VERSION 5.7 ;
  NOWIREEXTENSIONATPIN ON ;
  DIVIDERCHAR "/" ;
  BUSBITCHARS "[]" ;
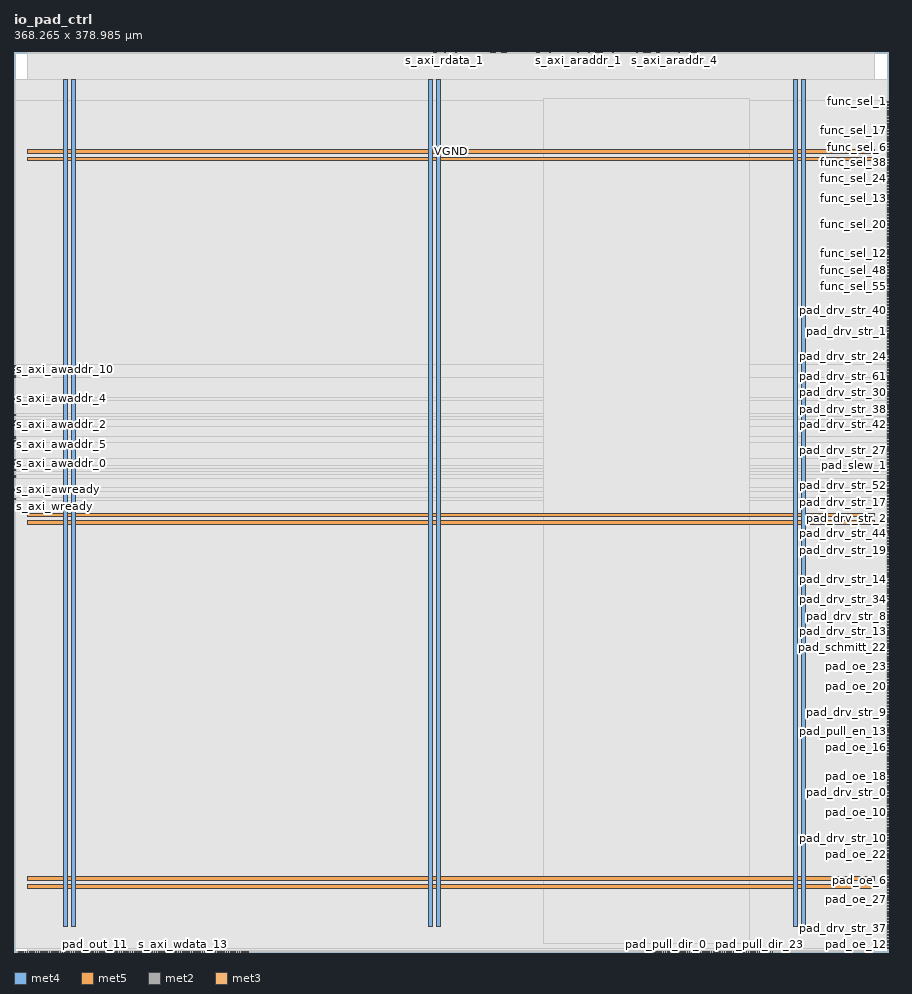
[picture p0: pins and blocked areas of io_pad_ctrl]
MACRO io_pad_ctrl
  CLASS BLOCK ;
  FOREIGN io_pad_ctrl ;
  ORIGIN 0.000 0.000 ;
  SIZE 368.265 BY 378.985 ;
  PIN VGND
    DIRECTION INOUT ;
    USE GROUND ;
    PORT
      LAYER met4 ;
        RECT 24.340 10.640 25.940 367.440 ;
    END
    PORT
      LAYER met4 ;
        RECT 177.940 10.640 179.540 367.440 ;
    END
    PORT
      LAYER met4 ;
        RECT 331.540 10.640 333.140 367.440 ;
    END
    PORT
      LAYER met5 ;
        RECT 5.520 30.030 362.480 31.630 ;
    END
    PORT
      LAYER met5 ;
        RECT 5.520 183.210 362.480 184.810 ;
    END
    PORT
      LAYER met5 ;
        RECT 5.520 336.390 362.480 337.990 ;
    END
  END VGND
  PIN VPWR
    DIRECTION INOUT ;
    USE POWER ;
    PORT
      LAYER met4 ;
        RECT 21.040 10.640 22.640 367.440 ;
    END
    PORT
      LAYER met4 ;
        RECT 174.640 10.640 176.240 367.440 ;
    END
    PORT
      LAYER met4 ;
        RECT 328.240 10.640 329.840 367.440 ;
    END
    PORT
      LAYER met5 ;
        RECT 5.520 26.730 362.480 28.330 ;
    END
    PORT
      LAYER met5 ;
        RECT 5.520 179.910 362.480 181.510 ;
    END
    PORT
      LAYER met5 ;
        RECT 5.520 333.090 362.480 334.690 ;
    END
  END VPWR
  PIN clk
    DIRECTION INPUT ;
    USE SIGNAL ;
    ANTENNAGATEAREA 1.286700 ;
    ANTENNADIFFAREA 0.434700 ;
    PORT
      LAYER met2 ;
        RECT 36.890 0.000 37.170 0.280 ;
    END
  END clk
  PIN func_sel_0
    DIRECTION OUTPUT ;
    USE SIGNAL ;
    ANTENNAGATEAREA 0.434700 ;
    ANTENNADIFFAREA 0.775300 ;
    PORT
      LAYER met3 ;
        RECT 367.665 243.480 368.265 244.080 ;
    END
  END func_sel_0
  PIN func_sel_1
    DIRECTION OUTPUT ;
    USE SIGNAL ;
    ANTENNAGATEAREA 0.434700 ;
    ANTENNADIFFAREA 0.775300 ;
    PORT
      LAYER met3 ;
        RECT 367.665 357.720 368.265 358.320 ;
    END
  END func_sel_1
  PIN func_sel_10
    DIRECTION OUTPUT ;
    USE SIGNAL ;
    ANTENNAGATEAREA 0.434700 ;
    ANTENNADIFFAREA 0.775300 ;
    PORT
      LAYER met3 ;
        RECT 367.665 341.400 368.265 342.000 ;
    END
  END func_sel_10
  PIN func_sel_11
    DIRECTION OUTPUT ;
    USE SIGNAL ;
    ANTENNAGATEAREA 0.434700 ;
    ANTENNADIFFAREA 0.775300 ;
    PORT
      LAYER met3 ;
        RECT 367.665 287.000 368.265 287.600 ;
    END
  END func_sel_11
  PIN func_sel_12
    DIRECTION OUTPUT ;
    USE SIGNAL ;
    ANTENNAGATEAREA 0.434700 ;
    ANTENNADIFFAREA 0.775300 ;
    PORT
      LAYER met3 ;
        RECT 367.665 293.800 368.265 294.400 ;
    END
  END func_sel_12
  PIN func_sel_13
    DIRECTION OUTPUT ;
    USE SIGNAL ;
    ANTENNAGATEAREA 0.434700 ;
    ANTENNADIFFAREA 0.775300 ;
    PORT
      LAYER met3 ;
        RECT 367.665 316.920 368.265 317.520 ;
    END
  END func_sel_13
  PIN func_sel_14
    DIRECTION OUTPUT ;
    USE SIGNAL ;
    ANTENNAGATEAREA 0.434700 ;
    ANTENNADIFFAREA 0.775300 ;
    PORT
      LAYER met3 ;
        RECT 367.665 342.760 368.265 343.360 ;
    END
  END func_sel_14
  PIN func_sel_15
    DIRECTION OUTPUT ;
    USE SIGNAL ;
    ANTENNAGATEAREA 0.434700 ;
    ANTENNADIFFAREA 0.775300 ;
    PORT
      LAYER met3 ;
        RECT 367.665 274.760 368.265 275.360 ;
    END
  END func_sel_15
  PIN func_sel_16
    DIRECTION OUTPUT ;
    USE SIGNAL ;
    ANTENNAGATEAREA 0.434700 ;
    ANTENNADIFFAREA 0.775300 ;
    PORT
      LAYER met3 ;
        RECT 367.665 318.280 368.265 318.880 ;
    END
  END func_sel_16
  PIN func_sel_17
    DIRECTION OUTPUT ;
    USE SIGNAL ;
    ANTENNAGATEAREA 0.434700 ;
    ANTENNADIFFAREA 0.775300 ;
    PORT
      LAYER met3 ;
        RECT 367.665 345.480 368.265 346.080 ;
    END
  END func_sel_17
  PIN func_sel_18
    DIRECTION OUTPUT ;
    USE SIGNAL ;
    ANTENNAGATEAREA 0.434700 ;
    ANTENNADIFFAREA 0.775300 ;
    PORT
      LAYER met3 ;
        RECT 367.665 344.120 368.265 344.720 ;
    END
  END func_sel_18
  PIN func_sel_19
    DIRECTION OUTPUT ;
    USE SIGNAL ;
    ANTENNAGATEAREA 0.434700 ;
    ANTENNADIFFAREA 0.775300 ;
    PORT
      LAYER met3 ;
        RECT 367.665 319.640 368.265 320.240 ;
    END
  END func_sel_19
  PIN func_sel_2
    DIRECTION OUTPUT ;
    USE SIGNAL ;
    ANTENNAGATEAREA 0.434700 ;
    ANTENNADIFFAREA 0.775300 ;
    PORT
      LAYER met3 ;
        RECT 367.665 280.200 368.265 280.800 ;
    END
  END func_sel_2
  PIN func_sel_20
    DIRECTION OUTPUT ;
    USE SIGNAL ;
    ANTENNAGATEAREA 0.434700 ;
    ANTENNADIFFAREA 0.775300 ;
    PORT
      LAYER met3 ;
        RECT 367.665 306.040 368.265 306.640 ;
    END
  END func_sel_20
  PIN func_sel_21
    DIRECTION OUTPUT ;
    USE SIGNAL ;
    ANTENNAGATEAREA 0.434700 ;
    ANTENNADIFFAREA 0.775300 ;
    PORT
      LAYER met3 ;
        RECT 367.665 352.280 368.265 352.880 ;
    END
  END func_sel_21
  PIN func_sel_22
    DIRECTION OUTPUT ;
    USE SIGNAL ;
    ANTENNAGATEAREA 0.434700 ;
    ANTENNADIFFAREA 0.775300 ;
    PORT
      LAYER met3 ;
        RECT 367.665 331.880 368.265 332.480 ;
    END
  END func_sel_22
  PIN func_sel_23
    DIRECTION OUTPUT ;
    USE SIGNAL ;
    ANTENNAGATEAREA 0.434700 ;
    ANTENNADIFFAREA 0.775300 ;
    PORT
      LAYER met3 ;
        RECT 367.665 301.960 368.265 302.560 ;
    END
  END func_sel_23
  PIN func_sel_24
    DIRECTION OUTPUT ;
    USE SIGNAL ;
    ANTENNAGATEAREA 0.434700 ;
    ANTENNADIFFAREA 0.775300 ;
    PORT
      LAYER met3 ;
        RECT 367.665 322.360 368.265 322.960 ;
    END
  END func_sel_24
  PIN func_sel_25
    DIRECTION OUTPUT ;
    USE SIGNAL ;
    ANTENNAGATEAREA 0.434700 ;
    ANTENNADIFFAREA 0.775300 ;
    PORT
      LAYER met3 ;
        RECT 367.665 346.840 368.265 347.440 ;
    END
  END func_sel_25
  PIN func_sel_26
    DIRECTION OUTPUT ;
    USE SIGNAL ;
    ANTENNAGATEAREA 0.434700 ;
    ANTENNADIFFAREA 0.775300 ;
    PORT
      LAYER met3 ;
        RECT 367.665 348.200 368.265 348.800 ;
    END
  END func_sel_26
  PIN func_sel_27
    DIRECTION OUTPUT ;
    USE SIGNAL ;
    ANTENNAGATEAREA 0.434700 ;
    ANTENNADIFFAREA 0.775300 ;
    PORT
      LAYER met3 ;
        RECT 367.665 323.720 368.265 324.320 ;
    END
  END func_sel_27
  PIN func_sel_28
    DIRECTION OUTPUT ;
    USE SIGNAL ;
    ANTENNAGATEAREA 0.434700 ;
    ANTENNADIFFAREA 0.775300 ;
    PORT
      LAYER met3 ;
        RECT 367.665 307.400 368.265 308.000 ;
    END
  END func_sel_28
  PIN func_sel_29
    DIRECTION OUTPUT ;
    USE SIGNAL ;
    ANTENNAGATEAREA 0.434700 ;
    ANTENNADIFFAREA 0.775300 ;
    PORT
      LAYER met3 ;
        RECT 367.665 291.080 368.265 291.680 ;
    END
  END func_sel_29
  PIN func_sel_3
    DIRECTION OUTPUT ;
    USE SIGNAL ;
    ANTENNAGATEAREA 0.434700 ;
    ANTENNADIFFAREA 0.775300 ;
    PORT
      LAYER met3 ;
        RECT 367.665 353.640 368.265 354.240 ;
    END
  END func_sel_3
  PIN func_sel_30
    DIRECTION OUTPUT ;
    USE SIGNAL ;
    ANTENNAGATEAREA 0.434700 ;
    ANTENNADIFFAREA 0.775300 ;
    PORT
      LAYER met3 ;
        RECT 367.665 292.440 368.265 293.040 ;
    END
  END func_sel_30
  PIN func_sel_31
    DIRECTION OUTPUT ;
    USE SIGNAL ;
    ANTENNAGATEAREA 0.434700 ;
    ANTENNADIFFAREA 0.775300 ;
    PORT
      LAYER met3 ;
        RECT 367.665 276.120 368.265 276.720 ;
    END
  END func_sel_31
  PIN func_sel_32
    DIRECTION OUTPUT ;
    USE SIGNAL ;
    ANTENNAGATEAREA 0.434700 ;
    ANTENNADIFFAREA 0.775300 ;
    PORT
      LAYER met3 ;
        RECT 367.665 326.440 368.265 327.040 ;
    END
  END func_sel_32
  PIN func_sel_33
    DIRECTION OUTPUT ;
    USE SIGNAL ;
    ANTENNAGATEAREA 0.434700 ;
    ANTENNADIFFAREA 0.775300 ;
    PORT
      LAYER met3 ;
        RECT 367.665 310.120 368.265 310.720 ;
    END
  END func_sel_33
  PIN func_sel_34
    DIRECTION OUTPUT ;
    USE SIGNAL ;
    ANTENNAGATEAREA 0.434700 ;
    ANTENNADIFFAREA 0.775300 ;
    PORT
      LAYER met3 ;
        RECT 367.665 349.560 368.265 350.160 ;
    END
  END func_sel_34
  PIN func_sel_35
    DIRECTION OUTPUT ;
    USE SIGNAL ;
    ANTENNAGATEAREA 0.434700 ;
    ANTENNADIFFAREA 0.775300 ;
    PORT
      LAYER met3 ;
        RECT 367.665 327.800 368.265 328.400 ;
    END
  END func_sel_35
  PIN func_sel_36
    DIRECTION OUTPUT ;
    USE SIGNAL ;
    ANTENNAGATEAREA 0.434700 ;
    ANTENNADIFFAREA 0.775300 ;
    PORT
      LAYER met3 ;
        RECT 367.665 295.160 368.265 295.760 ;
    END
  END func_sel_36
  PIN func_sel_37
    DIRECTION OUTPUT ;
    USE SIGNAL ;
    ANTENNAGATEAREA 0.434700 ;
    ANTENNADIFFAREA 0.775300 ;
    PORT
      LAYER met3 ;
        RECT 367.665 297.880 368.265 298.480 ;
    END
  END func_sel_37
  PIN func_sel_38
    DIRECTION OUTPUT ;
    USE SIGNAL ;
    ANTENNAGATEAREA 0.434700 ;
    ANTENNADIFFAREA 0.775300 ;
    PORT
      LAYER met3 ;
        RECT 367.665 329.160 368.265 329.760 ;
    END
  END func_sel_38
  PIN func_sel_39
    DIRECTION OUTPUT ;
    USE SIGNAL ;
    ANTENNAGATEAREA 0.434700 ;
    ANTENNADIFFAREA 0.775300 ;
    PORT
      LAYER met3 ;
        RECT 367.665 312.840 368.265 313.440 ;
    END
  END func_sel_39
  PIN func_sel_4
    DIRECTION OUTPUT ;
    USE SIGNAL ;
    ANTENNAGATEAREA 0.434700 ;
    ANTENNADIFFAREA 0.775300 ;
    PORT
      LAYER met3 ;
        RECT 367.665 296.520 368.265 297.120 ;
    END
  END func_sel_4
  PIN func_sel_40
    DIRECTION OUTPUT ;
    USE SIGNAL ;
    ANTENNAGATEAREA 0.434700 ;
    ANTENNADIFFAREA 0.775300 ;
    PORT
      LAYER met3 ;
        RECT 367.665 330.520 368.265 331.120 ;
    END
  END func_sel_40
  PIN func_sel_41
    DIRECTION OUTPUT ;
    USE SIGNAL ;
    ANTENNAGATEAREA 0.434700 ;
    ANTENNADIFFAREA 0.775300 ;
    PORT
      LAYER met3 ;
        RECT 367.665 355.000 368.265 355.600 ;
    END
  END func_sel_41
  PIN func_sel_42
    DIRECTION OUTPUT ;
    USE SIGNAL ;
    ANTENNAGATEAREA 0.434700 ;
    ANTENNADIFFAREA 0.775300 ;
    PORT
      LAYER met3 ;
        RECT 367.665 281.560 368.265 282.160 ;
    END
  END func_sel_42
  PIN func_sel_43
    DIRECTION OUTPUT ;
    USE SIGNAL ;
    ANTENNAGATEAREA 0.434700 ;
    ANTENNADIFFAREA 0.775300 ;
    PORT
      LAYER met3 ;
        RECT 367.665 356.360 368.265 356.960 ;
    END
  END func_sel_43
  PIN func_sel_44
    DIRECTION OUTPUT ;
    USE SIGNAL ;
    ANTENNAGATEAREA 0.434700 ;
    ANTENNADIFFAREA 0.775300 ;
    PORT
      LAYER met3 ;
        RECT 367.665 315.560 368.265 316.160 ;
    END
  END func_sel_44
  PIN func_sel_45
    DIRECTION OUTPUT ;
    USE SIGNAL ;
    ANTENNAGATEAREA 0.434700 ;
    ANTENNADIFFAREA 0.775300 ;
    PORT
      LAYER met3 ;
        RECT 367.665 299.240 368.265 299.840 ;
    END
  END func_sel_45
  PIN func_sel_46
    DIRECTION OUTPUT ;
    USE SIGNAL ;
    ANTENNAGATEAREA 0.434700 ;
    ANTENNADIFFAREA 0.775300 ;
    PORT
      LAYER met3 ;
        RECT 367.665 333.240 368.265 333.840 ;
    END
  END func_sel_46
  PIN func_sel_47
    DIRECTION OUTPUT ;
    USE SIGNAL ;
    ANTENNAGATEAREA 0.434700 ;
    ANTENNADIFFAREA 0.775300 ;
    PORT
      LAYER met3 ;
        RECT 367.665 300.600 368.265 301.200 ;
    END
  END func_sel_47
  PIN func_sel_48
    DIRECTION OUTPUT ;
    USE SIGNAL ;
    ANTENNAGATEAREA 0.434700 ;
    ANTENNADIFFAREA 0.775300 ;
    PORT
      LAYER met3 ;
        RECT 367.665 289.720 368.265 290.320 ;
    END
  END func_sel_48
  PIN func_sel_49
    DIRECTION OUTPUT ;
    USE SIGNAL ;
    ANTENNAGATEAREA 0.434700 ;
    ANTENNADIFFAREA 0.775300 ;
    PORT
      LAYER met3 ;
        RECT 367.665 334.600 368.265 335.200 ;
    END
  END func_sel_49
  PIN func_sel_5
    DIRECTION OUTPUT ;
    USE SIGNAL ;
    ANTENNAGATEAREA 0.434700 ;
    ANTENNADIFFAREA 0.775300 ;
    PORT
      LAYER met3 ;
        RECT 367.665 304.680 368.265 305.280 ;
    END
  END func_sel_5
  PIN func_sel_50
    DIRECTION OUTPUT ;
    USE SIGNAL ;
    ANTENNAGATEAREA 0.434700 ;
    ANTENNADIFFAREA 0.775300 ;
    PORT
      LAYER met3 ;
        RECT 367.665 303.320 368.265 303.920 ;
    END
  END func_sel_50
  PIN func_sel_51
    DIRECTION OUTPUT ;
    USE SIGNAL ;
    ANTENNAGATEAREA 0.434700 ;
    ANTENNADIFFAREA 0.775300 ;
    PORT
      LAYER met3 ;
        RECT 367.665 278.840 368.265 279.440 ;
    END
  END func_sel_51
  PIN func_sel_52
    DIRECTION OUTPUT ;
    USE SIGNAL ;
    ANTENNAGATEAREA 0.434700 ;
    ANTENNADIFFAREA 0.775300 ;
    PORT
      LAYER met3 ;
        RECT 367.665 335.960 368.265 336.560 ;
    END
  END func_sel_52
  PIN func_sel_53
    DIRECTION OUTPUT ;
    USE SIGNAL ;
    ANTENNAGATEAREA 0.434700 ;
    ANTENNADIFFAREA 0.775300 ;
    PORT
      LAYER met3 ;
        RECT 367.665 288.360 368.265 288.960 ;
    END
  END func_sel_53
  PIN func_sel_54
    DIRECTION OUTPUT ;
    USE SIGNAL ;
    ANTENNAGATEAREA 0.434700 ;
    ANTENNADIFFAREA 0.775300 ;
    PORT
      LAYER met3 ;
        RECT 367.665 337.320 368.265 337.920 ;
    END
  END func_sel_54
  PIN func_sel_55
    DIRECTION OUTPUT ;
    USE SIGNAL ;
    ANTENNAGATEAREA 0.434700 ;
    ANTENNADIFFAREA 0.775300 ;
    PORT
      LAYER met3 ;
        RECT 367.665 282.920 368.265 283.520 ;
    END
  END func_sel_55
  PIN func_sel_56
    DIRECTION OUTPUT ;
    USE SIGNAL ;
    ANTENNAGATEAREA 0.434700 ;
    ANTENNADIFFAREA 0.775300 ;
    PORT
      LAYER met3 ;
        RECT 367.665 340.040 368.265 340.640 ;
    END
  END func_sel_56
  PIN func_sel_57
    DIRECTION OUTPUT ;
    USE SIGNAL ;
    ANTENNAGATEAREA 0.434700 ;
    ANTENNADIFFAREA 0.775300 ;
    PORT
      LAYER met3 ;
        RECT 367.665 321.000 368.265 321.600 ;
    END
  END func_sel_57
  PIN func_sel_58
    DIRECTION OUTPUT ;
    USE SIGNAL ;
    ANTENNAGATEAREA 0.434700 ;
    ANTENNADIFFAREA 0.775300 ;
    PORT
      LAYER met3 ;
        RECT 367.665 308.760 368.265 309.360 ;
    END
  END func_sel_58
  PIN func_sel_59
    DIRECTION OUTPUT ;
    USE SIGNAL ;
    ANTENNAGATEAREA 0.434700 ;
    ANTENNADIFFAREA 0.775300 ;
    PORT
      LAYER met3 ;
        RECT 367.665 285.640 368.265 286.240 ;
    END
  END func_sel_59
  PIN func_sel_6
    DIRECTION OUTPUT ;
    USE SIGNAL ;
    ANTENNAGATEAREA 0.434700 ;
    ANTENNADIFFAREA 0.775300 ;
    PORT
      LAYER met3 ;
        RECT 367.665 338.680 368.265 339.280 ;
    END
  END func_sel_6
  PIN func_sel_60
    DIRECTION OUTPUT ;
    USE SIGNAL ;
    ANTENNAGATEAREA 0.434700 ;
    ANTENNADIFFAREA 0.775300 ;
    PORT
      LAYER met3 ;
        RECT 367.665 277.480 368.265 278.080 ;
    END
  END func_sel_60
  PIN func_sel_61
    DIRECTION OUTPUT ;
    USE SIGNAL ;
    ANTENNAGATEAREA 0.434700 ;
    ANTENNADIFFAREA 0.775300 ;
    PORT
      LAYER met3 ;
        RECT 367.665 311.480 368.265 312.080 ;
    END
  END func_sel_61
  PIN func_sel_62
    DIRECTION OUTPUT ;
    USE SIGNAL ;
    ANTENNAGATEAREA 0.434700 ;
    ANTENNADIFFAREA 0.775300 ;
    PORT
      LAYER met3 ;
        RECT 367.665 273.400 368.265 274.000 ;
    END
  END func_sel_62
  PIN func_sel_63
    DIRECTION OUTPUT ;
    USE SIGNAL ;
    ANTENNAGATEAREA 0.434700 ;
    ANTENNADIFFAREA 0.775300 ;
    PORT
      LAYER met3 ;
        RECT 367.665 350.920 368.265 351.520 ;
    END
  END func_sel_63
  PIN func_sel_7
    DIRECTION OUTPUT ;
    USE SIGNAL ;
    ANTENNAGATEAREA 0.434700 ;
    ANTENNADIFFAREA 0.775300 ;
    PORT
      LAYER met3 ;
        RECT 367.665 284.280 368.265 284.880 ;
    END
  END func_sel_7
  PIN func_sel_8
    DIRECTION OUTPUT ;
    USE SIGNAL ;
    ANTENNAGATEAREA 0.434700 ;
    ANTENNADIFFAREA 0.775300 ;
    PORT
      LAYER met3 ;
        RECT 367.665 314.200 368.265 314.800 ;
    END
  END func_sel_8
  PIN func_sel_9
    DIRECTION OUTPUT ;
    USE SIGNAL ;
    ANTENNAGATEAREA 0.434700 ;
    ANTENNADIFFAREA 0.775300 ;
    PORT
      LAYER met3 ;
        RECT 367.665 325.080 368.265 325.680 ;
    END
  END func_sel_9
  PIN pad_drv_str_0
    DIRECTION OUTPUT ;
    USE SIGNAL ;
    ANTENNAGATEAREA 0.434700 ;
    ANTENNADIFFAREA 0.434700 ;
    PORT
      LAYER met3 ;
        RECT 367.665 66.680 368.265 67.280 ;
    END
  END pad_drv_str_0
  PIN pad_drv_str_1
    DIRECTION OUTPUT ;
    USE SIGNAL ;
    ANTENNAGATEAREA 0.434700 ;
    ANTENNADIFFAREA 0.775300 ;
    PORT
      LAYER met3 ;
        RECT 367.665 261.160 368.265 261.760 ;
    END
  END pad_drv_str_1
  PIN pad_drv_str_10
    DIRECTION OUTPUT ;
    USE SIGNAL ;
    ANTENNAGATEAREA 0.434700 ;
    ANTENNADIFFAREA 0.775300 ;
    PORT
      LAYER met3 ;
        RECT 367.665 47.640 368.265 48.240 ;
    END
  END pad_drv_str_10
  PIN pad_drv_str_11
    DIRECTION OUTPUT ;
    USE SIGNAL ;
    ANTENNAGATEAREA 0.434700 ;
    ANTENNADIFFAREA 0.775300 ;
    PORT
      LAYER met3 ;
        RECT 367.665 25.880 368.265 26.480 ;
    END
  END pad_drv_str_11
  PIN pad_drv_str_12
    DIRECTION OUTPUT ;
    USE SIGNAL ;
    ANTENNAGATEAREA 0.434700 ;
    ANTENNADIFFAREA 0.775300 ;
    PORT
      LAYER met3 ;
        RECT 367.665 262.520 368.265 263.120 ;
    END
  END pad_drv_str_12
  PIN pad_drv_str_13
    DIRECTION OUTPUT ;
    USE SIGNAL ;
    ANTENNAGATEAREA 0.434700 ;
    ANTENNADIFFAREA 0.775300 ;
    PORT
      LAYER met3 ;
        RECT 367.665 134.680 368.265 135.280 ;
    END
  END pad_drv_str_13
  PIN pad_drv_str_14
    DIRECTION OUTPUT ;
    USE SIGNAL ;
    ANTENNAGATEAREA 0.434700 ;
    ANTENNADIFFAREA 0.775300 ;
    PORT
      LAYER met3 ;
        RECT 367.665 156.440 368.265 157.040 ;
    END
  END pad_drv_str_14
  PIN pad_drv_str_15
    DIRECTION OUTPUT ;
    USE SIGNAL ;
    ANTENNAGATEAREA 0.434700 ;
    ANTENNADIFFAREA 0.775300 ;
    PORT
      LAYER met3 ;
        RECT 367.665 183.640 368.265 184.240 ;
    END
  END pad_drv_str_15
  PIN pad_drv_str_16
    DIRECTION OUTPUT ;
    USE SIGNAL ;
    ANTENNAGATEAREA 0.434700 ;
    ANTENNADIFFAREA 0.775300 ;
    PORT
      LAYER met3 ;
        RECT 367.665 146.920 368.265 147.520 ;
    END
  END pad_drv_str_16
  PIN pad_drv_str_17
    DIRECTION OUTPUT ;
    USE SIGNAL ;
    ANTENNAGATEAREA 0.434700 ;
    ANTENNADIFFAREA 0.775300 ;
    PORT
      LAYER met3 ;
        RECT 367.665 189.080 368.265 189.680 ;
    END
  END pad_drv_str_17
  PIN pad_drv_str_18
    DIRECTION OUTPUT ;
    USE SIGNAL ;
    ANTENNAGATEAREA 0.434700 ;
    ANTENNADIFFAREA 0.775300 ;
    PORT
      LAYER met3 ;
        RECT 367.665 157.800 368.265 158.400 ;
    END
  END pad_drv_str_18
  PIN pad_drv_str_19
    DIRECTION OUTPUT ;
    USE SIGNAL ;
    ANTENNAGATEAREA 0.434700 ;
    ANTENNADIFFAREA 0.775300 ;
    PORT
      LAYER met3 ;
        RECT 367.665 168.680 368.265 169.280 ;
    END
  END pad_drv_str_19
  PIN pad_drv_str_2
    DIRECTION OUTPUT ;
    USE SIGNAL ;
    ANTENNAGATEAREA 0.434700 ;
    ANTENNADIFFAREA 0.775300 ;
    PORT
      LAYER met3 ;
        RECT 367.665 182.280 368.265 182.880 ;
    END
  END pad_drv_str_2
  PIN pad_drv_str_20
    DIRECTION OUTPUT ;
    USE SIGNAL ;
    ANTENNAGATEAREA 0.434700 ;
    ANTENNADIFFAREA 0.775300 ;
    PORT
      LAYER met3 ;
        RECT 367.665 165.960 368.265 166.560 ;
    END
  END pad_drv_str_20
  PIN pad_drv_str_21
    DIRECTION OUTPUT ;
    USE SIGNAL ;
    ANTENNAGATEAREA 0.434700 ;
    ANTENNADIFFAREA 0.775300 ;
    PORT
      LAYER met3 ;
        RECT 367.665 185.000 368.265 185.600 ;
    END
  END pad_drv_str_21
  PIN pad_drv_str_22
    DIRECTION OUTPUT ;
    USE SIGNAL ;
    ANTENNAGATEAREA 0.434700 ;
    ANTENNADIFFAREA 0.775300 ;
    PORT
      LAYER met3 ;
        RECT 367.665 171.400 368.265 172.000 ;
    END
  END pad_drv_str_22
  PIN pad_drv_str_23
    DIRECTION OUTPUT ;
    USE SIGNAL ;
    ANTENNAGATEAREA 0.434700 ;
    ANTENNADIFFAREA 0.775300 ;
    PORT
      LAYER met3 ;
        RECT 367.665 190.440 368.265 191.040 ;
    END
  END pad_drv_str_23
  PIN pad_drv_str_24
    DIRECTION OUTPUT ;
    USE SIGNAL ;
    ANTENNAGATEAREA 0.434700 ;
    ANTENNADIFFAREA 0.775300 ;
    PORT
      LAYER met3 ;
        RECT 367.665 250.280 368.265 250.880 ;
    END
  END pad_drv_str_24
  PIN pad_drv_str_25
    DIRECTION OUTPUT ;
    USE SIGNAL ;
    ANTENNAGATEAREA 0.434700 ;
    ANTENNADIFFAREA 0.775300 ;
    PORT
      LAYER met3 ;
        RECT 367.665 155.080 368.265 155.680 ;
    END
  END pad_drv_str_25
  PIN pad_drv_str_26
    DIRECTION OUTPUT ;
    USE SIGNAL ;
    ANTENNAGATEAREA 0.434700 ;
    ANTENNADIFFAREA 0.775300 ;
    PORT
      LAYER met3 ;
        RECT 367.665 187.720 368.265 188.320 ;
    END
  END pad_drv_str_26
  PIN pad_drv_str_27
    DIRECTION OUTPUT ;
    USE SIGNAL ;
    ANTENNAGATEAREA 0.434700 ;
    ANTENNADIFFAREA 0.775300 ;
    PORT
      LAYER met3 ;
        RECT 367.665 210.840 368.265 211.440 ;
    END
  END pad_drv_str_27
  PIN pad_drv_str_28
    DIRECTION OUTPUT ;
    USE SIGNAL ;
    ANTENNAGATEAREA 0.434700 ;
    ANTENNADIFFAREA 0.775300 ;
    PORT
      LAYER met3 ;
        RECT 367.665 170.040 368.265 170.640 ;
    END
  END pad_drv_str_28
  PIN pad_drv_str_29
    DIRECTION OUTPUT ;
    USE SIGNAL ;
    ANTENNAGATEAREA 0.434700 ;
    ANTENNADIFFAREA 0.775300 ;
    PORT
      LAYER met3 ;
        RECT 367.665 167.320 368.265 167.920 ;
    END
  END pad_drv_str_29
  PIN pad_drv_str_3
    DIRECTION OUTPUT ;
    USE SIGNAL ;
    ANTENNAGATEAREA 0.434700 ;
    ANTENNADIFFAREA 0.775300 ;
    PORT
      LAYER met3 ;
        RECT 367.665 88.440 368.265 89.040 ;
    END
  END pad_drv_str_3
  PIN pad_drv_str_30
    DIRECTION OUTPUT ;
    USE SIGNAL ;
    ANTENNAGATEAREA 0.434700 ;
    ANTENNADIFFAREA 0.775300 ;
    PORT
      LAYER met3 ;
        RECT 367.665 235.320 368.265 235.920 ;
    END
  END pad_drv_str_30
  PIN pad_drv_str_31
    DIRECTION OUTPUT ;
    USE SIGNAL ;
    ANTENNAGATEAREA 0.434700 ;
    ANTENNADIFFAREA 0.775300 ;
    PORT
      LAYER met3 ;
        RECT 367.665 36.760 368.265 37.360 ;
    END
  END pad_drv_str_31
  PIN pad_drv_str_32
    DIRECTION OUTPUT ;
    USE SIGNAL ;
    ANTENNAGATEAREA 0.434700 ;
    ANTENNADIFFAREA 0.775300 ;
    PORT
      LAYER met3 ;
        RECT 367.665 153.720 368.265 154.320 ;
    END
  END pad_drv_str_32
  PIN pad_drv_str_33
    DIRECTION OUTPUT ;
    USE SIGNAL ;
    ANTENNAGATEAREA 0.434700 ;
    ANTENNADIFFAREA 0.775300 ;
    PORT
      LAYER met3 ;
        RECT 367.665 258.440 368.265 259.040 ;
    END
  END pad_drv_str_33
  PIN pad_drv_str_34
    DIRECTION OUTPUT ;
    USE SIGNAL ;
    ANTENNAGATEAREA 0.434700 ;
    ANTENNADIFFAREA 0.775300 ;
    PORT
      LAYER met3 ;
        RECT 367.665 148.280 368.265 148.880 ;
    END
  END pad_drv_str_34
  PIN pad_drv_str_35
    DIRECTION OUTPUT ;
    USE SIGNAL ;
    ANTENNAGATEAREA 0.434700 ;
    ANTENNADIFFAREA 0.775300 ;
    PORT
      LAYER met3 ;
        RECT 367.665 251.640 368.265 252.240 ;
    END
  END pad_drv_str_35
  PIN pad_drv_str_36
    DIRECTION OUTPUT ;
    USE SIGNAL ;
    ANTENNAGATEAREA 0.434700 ;
    ANTENNADIFFAREA 0.775300 ;
    PORT
      LAYER met3 ;
        RECT 367.665 163.240 368.265 163.840 ;
    END
  END pad_drv_str_36
  PIN pad_drv_str_37
    DIRECTION OUTPUT ;
    USE SIGNAL ;
    ANTENNAGATEAREA 0.434700 ;
    ANTENNADIFFAREA 0.775300 ;
    PORT
      LAYER met3 ;
        RECT 367.665 9.560 368.265 10.160 ;
    END
  END pad_drv_str_37
  PIN pad_drv_str_38
    DIRECTION OUTPUT ;
    USE SIGNAL ;
    ANTENNAGATEAREA 0.434700 ;
    ANTENNADIFFAREA 0.775300 ;
    PORT
      LAYER met3 ;
        RECT 367.665 231.240 368.265 231.840 ;
    END
  END pad_drv_str_38
  PIN pad_drv_str_39
    DIRECTION OUTPUT ;
    USE SIGNAL ;
    ANTENNAGATEAREA 0.434700 ;
    ANTENNADIFFAREA 0.775300 ;
    PORT
      LAYER met3 ;
        RECT 367.665 145.560 368.265 146.160 ;
    END
  END pad_drv_str_39
  PIN pad_drv_str_4
    DIRECTION OUTPUT ;
    USE SIGNAL ;
    ANTENNAGATEAREA 0.434700 ;
    ANTENNADIFFAREA 0.775300 ;
    PORT
      LAYER met3 ;
        RECT 367.665 159.160 368.265 159.760 ;
    END
  END pad_drv_str_4
  PIN pad_drv_str_40
    DIRECTION OUTPUT ;
    USE SIGNAL ;
    ANTENNAGATEAREA 0.434700 ;
    ANTENNADIFFAREA 0.775300 ;
    PORT
      LAYER met3 ;
        RECT 367.665 266.600 368.265 267.200 ;
    END
  END pad_drv_str_40
  PIN pad_drv_str_41
    DIRECTION OUTPUT ;
    USE SIGNAL ;
    ANTENNAGATEAREA 0.434700 ;
    ANTENNADIFFAREA 0.775300 ;
    PORT
      LAYER met3 ;
        RECT 367.665 232.600 368.265 233.200 ;
    END
  END pad_drv_str_41
  PIN pad_drv_str_42
    DIRECTION OUTPUT ;
    USE SIGNAL ;
    ANTENNAGATEAREA 0.434700 ;
    ANTENNADIFFAREA 0.775300 ;
    PORT
      LAYER met3 ;
        RECT 367.665 221.720 368.265 222.320 ;
    END
  END pad_drv_str_42
  PIN pad_drv_str_43
    DIRECTION OUTPUT ;
    USE SIGNAL ;
    ANTENNAGATEAREA 0.434700 ;
    ANTENNADIFFAREA 0.775300 ;
    PORT
      LAYER met3 ;
        RECT 367.665 161.880 368.265 162.480 ;
    END
  END pad_drv_str_43
  PIN pad_drv_str_44
    DIRECTION OUTPUT ;
    USE SIGNAL ;
    ANTENNAGATEAREA 0.434700 ;
    ANTENNADIFFAREA 0.775300 ;
    PORT
      LAYER met3 ;
        RECT 367.665 172.760 368.265 173.360 ;
    END
  END pad_drv_str_44
  PIN pad_drv_str_45
    DIRECTION OUTPUT ;
    USE SIGNAL ;
    ANTENNAGATEAREA 0.434700 ;
    ANTENNADIFFAREA 0.775300 ;
    PORT
      LAYER met3 ;
        RECT 367.665 152.360 368.265 152.960 ;
    END
  END pad_drv_str_45
  PIN pad_drv_str_46
    DIRECTION OUTPUT ;
    USE SIGNAL ;
    ANTENNAGATEAREA 0.434700 ;
    ANTENNADIFFAREA 0.775300 ;
    PORT
      LAYER met3 ;
        RECT 367.665 174.120 368.265 174.720 ;
    END
  END pad_drv_str_46
  PIN pad_drv_str_47
    DIRECTION OUTPUT ;
    USE SIGNAL ;
    ANTENNAGATEAREA 0.434700 ;
    ANTENNADIFFAREA 0.775300 ;
    PORT
      LAYER met3 ;
        RECT 367.665 270.680 368.265 271.280 ;
    END
  END pad_drv_str_47
  PIN pad_drv_str_48
    DIRECTION OUTPUT ;
    USE SIGNAL ;
    ANTENNAGATEAREA 0.434700 ;
    ANTENNADIFFAREA 0.775300 ;
    PORT
      LAYER met3 ;
        RECT 367.665 164.600 368.265 165.200 ;
    END
  END pad_drv_str_48
  PIN pad_drv_str_49
    DIRECTION OUTPUT ;
    USE SIGNAL ;
    ANTENNAGATEAREA 0.434700 ;
    ANTENNADIFFAREA 0.775300 ;
    PORT
      LAYER met3 ;
        RECT 367.665 236.680 368.265 237.280 ;
    END
  END pad_drv_str_49
  PIN pad_drv_str_5
    DIRECTION OUTPUT ;
    USE SIGNAL ;
    ANTENNAGATEAREA 0.434700 ;
    ANTENNADIFFAREA 0.775300 ;
    PORT
      LAYER met3 ;
        RECT 367.665 227.160 368.265 227.760 ;
    END
  END pad_drv_str_5
  PIN pad_drv_str_50
    DIRECTION OUTPUT ;
    USE SIGNAL ;
    ANTENNAGATEAREA 0.434700 ;
    ANTENNADIFFAREA 0.775300 ;
    PORT
      LAYER met3 ;
        RECT 367.665 248.920 368.265 249.520 ;
    END
  END pad_drv_str_50
  PIN pad_drv_str_51
    DIRECTION OUTPUT ;
    USE SIGNAL ;
    ANTENNAGATEAREA 0.434700 ;
    ANTENNADIFFAREA 0.775300 ;
    PORT
      LAYER met3 ;
        RECT 367.665 229.880 368.265 230.480 ;
    END
  END pad_drv_str_51
  PIN pad_drv_str_52
    DIRECTION OUTPUT ;
    USE SIGNAL ;
    ANTENNAGATEAREA 0.434700 ;
    ANTENNADIFFAREA 0.775300 ;
    PORT
      LAYER met3 ;
        RECT 367.665 193.160 368.265 193.760 ;
    END
  END pad_drv_str_52
  PIN pad_drv_str_53
    DIRECTION OUTPUT ;
    USE SIGNAL ;
    ANTENNAGATEAREA 0.434700 ;
    ANTENNADIFFAREA 0.775300 ;
    PORT
      LAYER met3 ;
        RECT 367.665 191.800 368.265 192.400 ;
    END
  END pad_drv_str_53
  PIN pad_drv_str_54
    DIRECTION OUTPUT ;
    USE SIGNAL ;
    ANTENNAGATEAREA 0.434700 ;
    ANTENNADIFFAREA 0.775300 ;
    PORT
      LAYER met3 ;
        RECT 367.665 151.000 368.265 151.600 ;
    END
  END pad_drv_str_54
  PIN pad_drv_str_55
    DIRECTION OUTPUT ;
    USE SIGNAL ;
    ANTENNAGATEAREA 0.434700 ;
    ANTENNADIFFAREA 0.775300 ;
    PORT
      LAYER met3 ;
        RECT 367.665 186.360 368.265 186.960 ;
    END
  END pad_drv_str_55
  PIN pad_drv_str_56
    DIRECTION OUTPUT ;
    USE SIGNAL ;
    ANTENNAGATEAREA 0.434700 ;
    ANTENNADIFFAREA 0.775300 ;
    PORT
      LAYER met3 ;
        RECT 367.665 176.840 368.265 177.440 ;
    END
  END pad_drv_str_56
  PIN pad_drv_str_57
    DIRECTION OUTPUT ;
    USE SIGNAL ;
    ANTENNAGATEAREA 0.434700 ;
    ANTENNADIFFAREA 0.775300 ;
    PORT
      LAYER met3 ;
        RECT 367.665 246.200 368.265 246.800 ;
    END
  END pad_drv_str_57
  PIN pad_drv_str_58
    DIRECTION OUTPUT ;
    USE SIGNAL ;
    ANTENNAGATEAREA 0.434700 ;
    ANTENNADIFFAREA 0.775300 ;
    PORT
      LAYER met3 ;
        RECT 367.665 224.440 368.265 225.040 ;
    END
  END pad_drv_str_58
  PIN pad_drv_str_59
    DIRECTION OUTPUT ;
    USE SIGNAL ;
    ANTENNAGATEAREA 0.434700 ;
    ANTENNADIFFAREA 0.775300 ;
    PORT
      LAYER met3 ;
        RECT 367.665 208.120 368.265 208.720 ;
    END
  END pad_drv_str_59
  PIN pad_drv_str_6
    DIRECTION OUTPUT ;
    USE SIGNAL ;
    ANTENNAGATEAREA 0.434700 ;
    ANTENNADIFFAREA 0.775300 ;
    PORT
      LAYER met3 ;
        RECT 367.665 269.320 368.265 269.920 ;
    END
  END pad_drv_str_6
  PIN pad_drv_str_60
    DIRECTION OUTPUT ;
    USE SIGNAL ;
    ANTENNAGATEAREA 0.434700 ;
    ANTENNADIFFAREA 0.775300 ;
    PORT
      LAYER met3 ;
        RECT 367.665 214.920 368.265 215.520 ;
    END
  END pad_drv_str_60
  PIN pad_drv_str_61
    DIRECTION OUTPUT ;
    USE SIGNAL ;
    ANTENNAGATEAREA 0.434700 ;
    ANTENNADIFFAREA 0.775300 ;
    PORT
      LAYER met3 ;
        RECT 367.665 242.120 368.265 242.720 ;
    END
  END pad_drv_str_61
  PIN pad_drv_str_62
    DIRECTION OUTPUT ;
    USE SIGNAL ;
    ANTENNAGATEAREA 0.434700 ;
    ANTENNADIFFAREA 0.775300 ;
    PORT
      LAYER met3 ;
        RECT 367.665 253.000 368.265 253.600 ;
    END
  END pad_drv_str_62
  PIN pad_drv_str_63
    DIRECTION OUTPUT ;
    USE SIGNAL ;
    ANTENNAGATEAREA 0.434700 ;
    ANTENNADIFFAREA 0.775300 ;
    PORT
      LAYER met3 ;
        RECT 367.665 228.520 368.265 229.120 ;
    END
  END pad_drv_str_63
  PIN pad_drv_str_7
    DIRECTION OUTPUT ;
    USE SIGNAL ;
    ANTENNAGATEAREA 0.434700 ;
    ANTENNADIFFAREA 0.775300 ;
    PORT
      LAYER met3 ;
        RECT 367.665 223.080 368.265 223.680 ;
    END
  END pad_drv_str_7
  PIN pad_drv_str_8
    DIRECTION OUTPUT ;
    USE SIGNAL ;
    ANTENNAGATEAREA 0.434700 ;
    ANTENNADIFFAREA 0.775300 ;
    PORT
      LAYER met3 ;
        RECT 367.665 144.200 368.265 144.800 ;
    END
  END pad_drv_str_8
  PIN pad_drv_str_9
    DIRECTION OUTPUT ;
    USE SIGNAL ;
    ANTENNAGATEAREA 0.434700 ;
    ANTENNADIFFAREA 0.775300 ;
    PORT
      LAYER met3 ;
        RECT 367.665 100.680 368.265 101.280 ;
    END
  END pad_drv_str_9
  PIN pad_in_0
    DIRECTION INPUT ;
    USE SIGNAL ;
    PORT
      LAYER met2 ;
        RECT 1.930 0.000 2.210 0.280 ;
    END
  END pad_in_0
  PIN pad_in_1
    DIRECTION INPUT ;
    USE SIGNAL ;
    PORT
      LAYER met2 ;
        RECT 2.850 0.000 3.130 0.280 ;
    END
  END pad_in_1
  PIN pad_in_10
    DIRECTION INPUT ;
    USE SIGNAL ;
    PORT
      LAYER met2 ;
        RECT 3.770 0.000 4.050 0.280 ;
    END
  END pad_in_10
  PIN pad_in_11
    DIRECTION INPUT ;
    USE SIGNAL ;
    PORT
      LAYER met2 ;
        RECT 4.690 0.000 4.970 0.280 ;
    END
  END pad_in_11
  PIN pad_in_12
    DIRECTION INPUT ;
    USE SIGNAL ;
    PORT
      LAYER met2 ;
        RECT 5.610 0.000 5.890 0.280 ;
    END
  END pad_in_12
  PIN pad_in_13
    DIRECTION INPUT ;
    USE SIGNAL ;
    PORT
      LAYER met2 ;
        RECT 6.530 0.000 6.810 0.280 ;
    END
  END pad_in_13
  PIN pad_in_14
    DIRECTION INPUT ;
    USE SIGNAL ;
    PORT
      LAYER met2 ;
        RECT 7.450 0.000 7.730 0.280 ;
    END
  END pad_in_14
  PIN pad_in_15
    DIRECTION INPUT ;
    USE SIGNAL ;
    PORT
      LAYER met2 ;
        RECT 8.370 0.000 8.650 0.280 ;
    END
  END pad_in_15
  PIN pad_in_16
    DIRECTION INPUT ;
    USE SIGNAL ;
    PORT
      LAYER met2 ;
        RECT 9.290 0.000 9.570 0.280 ;
    END
  END pad_in_16
  PIN pad_in_17
    DIRECTION INPUT ;
    USE SIGNAL ;
    PORT
      LAYER met2 ;
        RECT 10.210 0.000 10.490 0.280 ;
    END
  END pad_in_17
  PIN pad_in_18
    DIRECTION INPUT ;
    USE SIGNAL ;
    PORT
      LAYER met2 ;
        RECT 11.130 0.000 11.410 0.280 ;
    END
  END pad_in_18
  PIN pad_in_19
    DIRECTION INPUT ;
    USE SIGNAL ;
    PORT
      LAYER met2 ;
        RECT 12.050 0.000 12.330 0.280 ;
    END
  END pad_in_19
  PIN pad_in_2
    DIRECTION INPUT ;
    USE SIGNAL ;
    PORT
      LAYER met2 ;
        RECT 12.970 0.000 13.250 0.280 ;
    END
  END pad_in_2
  PIN pad_in_20
    DIRECTION INPUT ;
    USE SIGNAL ;
    PORT
      LAYER met2 ;
        RECT 13.890 0.000 14.170 0.280 ;
    END
  END pad_in_20
  PIN pad_in_21
    DIRECTION INPUT ;
    USE SIGNAL ;
    PORT
      LAYER met2 ;
        RECT 14.810 0.000 15.090 0.280 ;
    END
  END pad_in_21
  PIN pad_in_22
    DIRECTION INPUT ;
    USE SIGNAL ;
    PORT
      LAYER met2 ;
        RECT 15.730 0.000 16.010 0.280 ;
    END
  END pad_in_22
  PIN pad_in_23
    DIRECTION INPUT ;
    USE SIGNAL ;
    PORT
      LAYER met2 ;
        RECT 16.650 0.000 16.930 0.280 ;
    END
  END pad_in_23
  PIN pad_in_24
    DIRECTION INPUT ;
    USE SIGNAL ;
    PORT
      LAYER met2 ;
        RECT 17.570 0.000 17.850 0.280 ;
    END
  END pad_in_24
  PIN pad_in_25
    DIRECTION INPUT ;
    USE SIGNAL ;
    PORT
      LAYER met2 ;
        RECT 18.490 0.000 18.770 0.280 ;
    END
  END pad_in_25
  PIN pad_in_26
    DIRECTION INPUT ;
    USE SIGNAL ;
    PORT
      LAYER met2 ;
        RECT 19.410 0.000 19.690 0.280 ;
    END
  END pad_in_26
  PIN pad_in_27
    DIRECTION INPUT ;
    USE SIGNAL ;
    PORT
      LAYER met2 ;
        RECT 20.330 0.000 20.610 0.280 ;
    END
  END pad_in_27
  PIN pad_in_28
    DIRECTION INPUT ;
    USE SIGNAL ;
    PORT
      LAYER met2 ;
        RECT 21.250 0.000 21.530 0.280 ;
    END
  END pad_in_28
  PIN pad_in_29
    DIRECTION INPUT ;
    USE SIGNAL ;
    PORT
      LAYER met2 ;
        RECT 22.170 0.000 22.450 0.280 ;
    END
  END pad_in_29
  PIN pad_in_3
    DIRECTION INPUT ;
    USE SIGNAL ;
    PORT
      LAYER met2 ;
        RECT 23.090 0.000 23.370 0.280 ;
    END
  END pad_in_3
  PIN pad_in_30
    DIRECTION INPUT ;
    USE SIGNAL ;
    PORT
      LAYER met2 ;
        RECT 24.010 0.000 24.290 0.280 ;
    END
  END pad_in_30
  PIN pad_in_31
    DIRECTION INPUT ;
    USE SIGNAL ;
    PORT
      LAYER met2 ;
        RECT 24.930 0.000 25.210 0.280 ;
    END
  END pad_in_31
  PIN pad_in_4
    DIRECTION INPUT ;
    USE SIGNAL ;
    PORT
      LAYER met2 ;
        RECT 25.850 0.000 26.130 0.280 ;
    END
  END pad_in_4
  PIN pad_in_5
    DIRECTION INPUT ;
    USE SIGNAL ;
    PORT
      LAYER met2 ;
        RECT 26.770 0.000 27.050 0.280 ;
    END
  END pad_in_5
  PIN pad_in_6
    DIRECTION INPUT ;
    USE SIGNAL ;
    PORT
      LAYER met2 ;
        RECT 27.690 0.000 27.970 0.280 ;
    END
  END pad_in_6
  PIN pad_in_7
    DIRECTION INPUT ;
    USE SIGNAL ;
    PORT
      LAYER met2 ;
        RECT 28.610 0.000 28.890 0.280 ;
    END
  END pad_in_7
  PIN pad_in_8
    DIRECTION INPUT ;
    USE SIGNAL ;
    PORT
      LAYER met2 ;
        RECT 29.530 0.000 29.810 0.280 ;
    END
  END pad_in_8
  PIN pad_in_9
    DIRECTION INPUT ;
    USE SIGNAL ;
    PORT
      LAYER met2 ;
        RECT 30.450 0.000 30.730 0.280 ;
    END
  END pad_in_9
  PIN pad_oe_0
    DIRECTION OUTPUT ;
    USE SIGNAL ;
    ANTENNAGATEAREA 0.434700 ;
    ANTENNADIFFAREA 1.137600 ;
    PORT
      LAYER met3 ;
        RECT 367.665 15.000 368.265 15.600 ;
    END
  END pad_oe_0
  PIN pad_oe_1
    DIRECTION OUTPUT ;
    USE SIGNAL ;
    ANTENNAGATEAREA 0.434700 ;
    ANTENNADIFFAREA 1.137600 ;
    PORT
      LAYER met3 ;
        RECT 367.665 178.200 368.265 178.800 ;
    END
  END pad_oe_1
  PIN pad_oe_10
    DIRECTION OUTPUT ;
    USE SIGNAL ;
    ANTENNAGATEAREA 0.434700 ;
    ANTENNADIFFAREA 1.137600 ;
    PORT
      LAYER met3 ;
        RECT 367.665 58.520 368.265 59.120 ;
    END
  END pad_oe_10
  PIN pad_oe_11
    DIRECTION OUTPUT ;
    USE SIGNAL ;
    ANTENNAGATEAREA 0.434700 ;
    ANTENNADIFFAREA 1.137600 ;
    PORT
      LAYER met3 ;
        RECT 367.665 59.880 368.265 60.480 ;
    END
  END pad_oe_11
  PIN pad_oe_12
    DIRECTION OUTPUT ;
    USE SIGNAL ;
    ANTENNAGATEAREA 0.434700 ;
    ANTENNADIFFAREA 1.137600 ;
    PORT
      LAYER met3 ;
        RECT 367.665 4.120 368.265 4.720 ;
    END
  END pad_oe_12
  PIN pad_oe_13
    DIRECTION OUTPUT ;
    USE SIGNAL ;
    ANTENNAGATEAREA 0.434700 ;
    ANTENNADIFFAREA 1.137600 ;
    PORT
      LAYER met3 ;
        RECT 367.665 141.480 368.265 142.080 ;
    END
  END pad_oe_13
  PIN pad_oe_14
    DIRECTION OUTPUT ;
    USE SIGNAL ;
    ANTENNAGATEAREA 0.434700 ;
    ANTENNADIFFAREA 1.137600 ;
    PORT
      LAYER met3 ;
        RECT 367.665 12.280 368.265 12.880 ;
    END
  END pad_oe_14
  PIN pad_oe_15
    DIRECTION OUTPUT ;
    USE SIGNAL ;
    ANTENNAGATEAREA 0.434700 ;
    ANTENNADIFFAREA 1.137600 ;
    PORT
      LAYER met3 ;
        RECT 367.665 1.400 368.265 2.000 ;
    END
  END pad_oe_15
  PIN pad_oe_16
    DIRECTION OUTPUT ;
    USE SIGNAL ;
    ANTENNAGATEAREA 0.434700 ;
    ANTENNADIFFAREA 1.137600 ;
    PORT
      LAYER met3 ;
        RECT 367.665 85.720 368.265 86.320 ;
    END
  END pad_oe_16
  PIN pad_oe_17
    DIRECTION OUTPUT ;
    USE SIGNAL ;
    ANTENNAGATEAREA 0.434700 ;
    ANTENNADIFFAREA 1.137600 ;
    PORT
      LAYER met3 ;
        RECT 367.665 19.080 368.265 19.680 ;
    END
  END pad_oe_17
  PIN pad_oe_18
    DIRECTION OUTPUT ;
    USE SIGNAL ;
    ANTENNAGATEAREA 0.434700 ;
    ANTENNADIFFAREA 1.137600 ;
    PORT
      LAYER met3 ;
        RECT 367.665 73.480 368.265 74.080 ;
    END
  END pad_oe_18
  PIN pad_oe_19
    DIRECTION OUTPUT ;
    USE SIGNAL ;
    ANTENNAGATEAREA 0.434700 ;
    ANTENNADIFFAREA 1.137600 ;
    PORT
      LAYER met3 ;
        RECT 367.665 5.480 368.265 6.080 ;
    END
  END pad_oe_19
  PIN pad_oe_2
    DIRECTION OUTPUT ;
    USE SIGNAL ;
    ANTENNAGATEAREA 0.434700 ;
    ANTENNADIFFAREA 1.137600 ;
    PORT
      LAYER met3 ;
        RECT 367.665 6.840 368.265 7.440 ;
    END
  END pad_oe_2
  PIN pad_oe_20
    DIRECTION OUTPUT ;
    USE SIGNAL ;
    ANTENNAGATEAREA 0.434700 ;
    ANTENNADIFFAREA 1.137600 ;
    PORT
      LAYER met3 ;
        RECT 367.665 111.560 368.265 112.160 ;
    END
  END pad_oe_20
  PIN pad_oe_21
    DIRECTION OUTPUT ;
    USE SIGNAL ;
    ANTENNAGATEAREA 0.434700 ;
    ANTENNADIFFAREA 1.137600 ;
    PORT
      LAYER met3 ;
        RECT 367.665 2.760 368.265 3.360 ;
    END
  END pad_oe_21
  PIN pad_oe_22
    DIRECTION OUTPUT ;
    USE SIGNAL ;
    ANTENNAGATEAREA 0.434700 ;
    ANTENNADIFFAREA 1.137600 ;
    PORT
      LAYER met3 ;
        RECT 367.665 40.840 368.265 41.440 ;
    END
  END pad_oe_22
  PIN pad_oe_23
    DIRECTION OUTPUT ;
    USE SIGNAL ;
    ANTENNAGATEAREA 0.434700 ;
    ANTENNADIFFAREA 1.137600 ;
    PORT
      LAYER met3 ;
        RECT 367.665 117.000 368.265 117.600 ;
    END
  END pad_oe_23
  PIN pad_oe_24
    DIRECTION OUTPUT ;
    USE SIGNAL ;
    ANTENNAGATEAREA 0.434700 ;
    ANTENNADIFFAREA 1.137600 ;
    PORT
      LAYER met3 ;
        RECT 367.665 180.920 368.265 181.520 ;
    END
  END pad_oe_24
  PIN pad_oe_25
    DIRECTION OUTPUT ;
    USE SIGNAL ;
    ANTENNAGATEAREA 0.434700 ;
    ANTENNADIFFAREA 1.137600 ;
    PORT
      LAYER met3 ;
        RECT 367.665 16.360 368.265 16.960 ;
    END
  END pad_oe_25
  PIN pad_oe_26
    DIRECTION OUTPUT ;
    USE SIGNAL ;
    ANTENNAGATEAREA 0.434700 ;
    ANTENNADIFFAREA 1.137600 ;
    PORT
      LAYER met3 ;
        RECT 367.665 149.640 368.265 150.240 ;
    END
  END pad_oe_26
  PIN pad_oe_27
    DIRECTION OUTPUT ;
    USE SIGNAL ;
    ANTENNAGATEAREA 0.434700 ;
    ANTENNADIFFAREA 1.137600 ;
    PORT
      LAYER met3 ;
        RECT 367.665 21.800 368.265 22.400 ;
    END
  END pad_oe_27
  PIN pad_oe_28
    DIRECTION OUTPUT ;
    USE SIGNAL ;
    ANTENNAGATEAREA 0.434700 ;
    ANTENNADIFFAREA 1.137600 ;
    PORT
      LAYER met3 ;
        RECT 367.665 20.440 368.265 21.040 ;
    END
  END pad_oe_28
  PIN pad_oe_29
    DIRECTION OUTPUT ;
    USE SIGNAL ;
    ANTENNAGATEAREA 0.434700 ;
    ANTENNADIFFAREA 1.137600 ;
    PORT
      LAYER met3 ;
        RECT 367.665 17.720 368.265 18.320 ;
    END
  END pad_oe_29
  PIN pad_oe_3
    DIRECTION OUTPUT ;
    USE SIGNAL ;
    ANTENNAGATEAREA 0.434700 ;
    ANTENNADIFFAREA 1.137600 ;
    PORT
      LAYER met3 ;
        RECT 367.665 179.560 368.265 180.160 ;
    END
  END pad_oe_3
  PIN pad_oe_30
    DIRECTION OUTPUT ;
    USE SIGNAL ;
    ANTENNAGATEAREA 0.434700 ;
    ANTENNADIFFAREA 1.137600 ;
    PORT
      LAYER met3 ;
        RECT 367.665 13.640 368.265 14.240 ;
    END
  END pad_oe_30
  PIN pad_oe_31
    DIRECTION OUTPUT ;
    USE SIGNAL ;
    ANTENNAGATEAREA 0.434700 ;
    ANTENNADIFFAREA 1.137600 ;
    PORT
      LAYER met3 ;
        RECT 367.665 108.840 368.265 109.440 ;
    END
  END pad_oe_31
  PIN pad_oe_4
    DIRECTION OUTPUT ;
    USE SIGNAL ;
    ANTENNAGATEAREA 0.434700 ;
    ANTENNADIFFAREA 1.137600 ;
    PORT
      LAYER met3 ;
        RECT 367.665 160.520 368.265 161.120 ;
    END
  END pad_oe_4
  PIN pad_oe_5
    DIRECTION OUTPUT ;
    USE SIGNAL ;
    ANTENNAGATEAREA 0.434700 ;
    ANTENNADIFFAREA 1.137600 ;
    PORT
      LAYER met3 ;
        RECT 367.665 8.200 368.265 8.800 ;
    END
  END pad_oe_5
  PIN pad_oe_6
    DIRECTION OUTPUT ;
    USE SIGNAL ;
    ANTENNAGATEAREA 0.434700 ;
    ANTENNADIFFAREA 1.137600 ;
    PORT
      LAYER met3 ;
        RECT 367.665 29.960 368.265 30.560 ;
    END
  END pad_oe_6
  PIN pad_oe_7
    DIRECTION OUTPUT ;
    USE SIGNAL ;
    ANTENNAGATEAREA 0.434700 ;
    ANTENNADIFFAREA 1.137600 ;
    PORT
      LAYER met3 ;
        RECT 367.665 122.440 368.265 123.040 ;
    END
  END pad_oe_7
  PIN pad_oe_8
    DIRECTION OUTPUT ;
    USE SIGNAL ;
    ANTENNAGATEAREA 0.434700 ;
    ANTENNADIFFAREA 1.137600 ;
    PORT
      LAYER met3 ;
        RECT 367.665 119.720 368.265 120.320 ;
    END
  END pad_oe_8
  PIN pad_oe_9
    DIRECTION OUTPUT ;
    USE SIGNAL ;
    ANTENNAGATEAREA 0.434700 ;
    ANTENNADIFFAREA 1.137600 ;
    PORT
      LAYER met3 ;
        RECT 367.665 51.720 368.265 52.320 ;
    END
  END pad_oe_9
  PIN pad_out_0
    DIRECTION OUTPUT ;
    USE SIGNAL ;
    PORT
      LAYER met2 ;
        RECT 31.370 0.000 31.650 0.280 ;
    END
  END pad_out_0
  PIN pad_out_1
    DIRECTION OUTPUT ;
    USE SIGNAL ;
    PORT
      LAYER met2 ;
        RECT 32.290 0.000 32.570 0.280 ;
    END
  END pad_out_1
  PIN pad_out_10
    DIRECTION OUTPUT ;
    USE SIGNAL ;
    PORT
      LAYER met2 ;
        RECT 33.210 0.000 33.490 0.280 ;
    END
  END pad_out_10
  PIN pad_out_11
    DIRECTION OUTPUT ;
    USE SIGNAL ;
    PORT
      LAYER met2 ;
        RECT 34.130 0.000 34.410 0.280 ;
    END
  END pad_out_11
  PIN pad_out_12
    DIRECTION OUTPUT ;
    USE SIGNAL ;
    PORT
      LAYER met2 ;
        RECT 35.050 0.000 35.330 0.280 ;
    END
  END pad_out_12
  PIN pad_out_13
    DIRECTION OUTPUT ;
    USE SIGNAL ;
    PORT
      LAYER met2 ;
        RECT 35.970 0.000 36.250 0.280 ;
    END
  END pad_out_13
  PIN pad_out_14
    DIRECTION OUTPUT ;
    USE SIGNAL ;
    PORT
      LAYER met2 ;
        RECT 37.810 0.000 38.090 0.280 ;
    END
  END pad_out_14
  PIN pad_out_15
    DIRECTION OUTPUT ;
    USE SIGNAL ;
    PORT
      LAYER met2 ;
        RECT 38.730 0.000 39.010 0.280 ;
    END
  END pad_out_15
  PIN pad_out_16
    DIRECTION OUTPUT ;
    USE SIGNAL ;
    PORT
      LAYER met2 ;
        RECT 39.650 0.000 39.930 0.280 ;
    END
  END pad_out_16
  PIN pad_out_17
    DIRECTION OUTPUT ;
    USE SIGNAL ;
    PORT
      LAYER met2 ;
        RECT 40.570 0.000 40.850 0.280 ;
    END
  END pad_out_17
  PIN pad_out_18
    DIRECTION OUTPUT ;
    USE SIGNAL ;
    PORT
      LAYER met2 ;
        RECT 41.490 0.000 41.770 0.280 ;
    END
  END pad_out_18
  PIN pad_out_19
    DIRECTION OUTPUT ;
    USE SIGNAL ;
    PORT
      LAYER met2 ;
        RECT 42.410 0.000 42.690 0.280 ;
    END
  END pad_out_19
  PIN pad_out_2
    DIRECTION OUTPUT ;
    USE SIGNAL ;
    PORT
      LAYER met2 ;
        RECT 43.330 0.000 43.610 0.280 ;
    END
  END pad_out_2
  PIN pad_out_20
    DIRECTION OUTPUT ;
    USE SIGNAL ;
    PORT
      LAYER met2 ;
        RECT 44.250 0.000 44.530 0.280 ;
    END
  END pad_out_20
  PIN pad_out_21
    DIRECTION OUTPUT ;
    USE SIGNAL ;
    PORT
      LAYER met2 ;
        RECT 45.170 0.000 45.450 0.280 ;
    END
  END pad_out_21
  PIN pad_out_22
    DIRECTION OUTPUT ;
    USE SIGNAL ;
    PORT
      LAYER met2 ;
        RECT 46.090 0.000 46.370 0.280 ;
    END
  END pad_out_22
  PIN pad_out_23
    DIRECTION OUTPUT ;
    USE SIGNAL ;
    PORT
      LAYER met2 ;
        RECT 47.010 0.000 47.290 0.280 ;
    END
  END pad_out_23
  PIN pad_out_24
    DIRECTION OUTPUT ;
    USE SIGNAL ;
    PORT
      LAYER met2 ;
        RECT 47.930 0.000 48.210 0.280 ;
    END
  END pad_out_24
  PIN pad_out_25
    DIRECTION OUTPUT ;
    USE SIGNAL ;
    PORT
      LAYER met2 ;
        RECT 48.850 0.000 49.130 0.280 ;
    END
  END pad_out_25
  PIN pad_out_26
    DIRECTION OUTPUT ;
    USE SIGNAL ;
    PORT
      LAYER met2 ;
        RECT 49.770 0.000 50.050 0.280 ;
    END
  END pad_out_26
  PIN pad_out_27
    DIRECTION OUTPUT ;
    USE SIGNAL ;
    PORT
      LAYER met2 ;
        RECT 50.690 0.000 50.970 0.280 ;
    END
  END pad_out_27
  PIN pad_out_28
    DIRECTION OUTPUT ;
    USE SIGNAL ;
    PORT
      LAYER met2 ;
        RECT 51.610 0.000 51.890 0.280 ;
    END
  END pad_out_28
  PIN pad_out_29
    DIRECTION OUTPUT ;
    USE SIGNAL ;
    PORT
      LAYER met2 ;
        RECT 52.530 0.000 52.810 0.280 ;
    END
  END pad_out_29
  PIN pad_out_3
    DIRECTION OUTPUT ;
    USE SIGNAL ;
    PORT
      LAYER met2 ;
        RECT 53.450 0.000 53.730 0.280 ;
    END
  END pad_out_3
  PIN pad_out_30
    DIRECTION OUTPUT ;
    USE SIGNAL ;
    PORT
      LAYER met2 ;
        RECT 54.370 0.000 54.650 0.280 ;
    END
  END pad_out_30
  PIN pad_out_31
    DIRECTION OUTPUT ;
    USE SIGNAL ;
    PORT
      LAYER met2 ;
        RECT 55.290 0.000 55.570 0.280 ;
    END
  END pad_out_31
  PIN pad_out_4
    DIRECTION OUTPUT ;
    USE SIGNAL ;
    PORT
      LAYER met2 ;
        RECT 56.210 0.000 56.490 0.280 ;
    END
  END pad_out_4
  PIN pad_out_5
    DIRECTION OUTPUT ;
    USE SIGNAL ;
    PORT
      LAYER met2 ;
        RECT 57.130 0.000 57.410 0.280 ;
    END
  END pad_out_5
  PIN pad_out_6
    DIRECTION OUTPUT ;
    USE SIGNAL ;
    PORT
      LAYER met2 ;
        RECT 58.050 0.000 58.330 0.280 ;
    END
  END pad_out_6
  PIN pad_out_7
    DIRECTION OUTPUT ;
    USE SIGNAL ;
    PORT
      LAYER met2 ;
        RECT 58.970 0.000 59.250 0.280 ;
    END
  END pad_out_7
  PIN pad_out_8
    DIRECTION OUTPUT ;
    USE SIGNAL ;
    PORT
      LAYER met2 ;
        RECT 59.890 0.000 60.170 0.280 ;
    END
  END pad_out_8
  PIN pad_out_9
    DIRECTION OUTPUT ;
    USE SIGNAL ;
    PORT
      LAYER met2 ;
        RECT 60.810 0.000 61.090 0.280 ;
    END
  END pad_out_9
  PIN pad_pull_dir_0
    DIRECTION OUTPUT ;
    USE SIGNAL ;
    ANTENNAGATEAREA 0.434700 ;
    ANTENNADIFFAREA 1.137600 ;
    PORT
      LAYER met2 ;
        RECT 274.250 0.000 274.530 0.280 ;
    END
  END pad_pull_dir_0
  PIN pad_pull_dir_1
    DIRECTION OUTPUT ;
    USE SIGNAL ;
    ANTENNAGATEAREA 0.434700 ;
    ANTENNADIFFAREA 1.137600 ;
    PORT
      LAYER met2 ;
        RECT 284.370 0.000 284.650 0.280 ;
    END
  END pad_pull_dir_1
  PIN pad_pull_dir_10
    DIRECTION OUTPUT ;
    USE SIGNAL ;
    ANTENNAGATEAREA 0.434700 ;
    ANTENNADIFFAREA 1.137600 ;
    PORT
      LAYER met2 ;
        RECT 319.330 0.000 319.610 0.280 ;
    END
  END pad_pull_dir_10
  PIN pad_pull_dir_11
    DIRECTION OUTPUT ;
    USE SIGNAL ;
    ANTENNAGATEAREA 0.434700 ;
    ANTENNADIFFAREA 1.137600 ;
    PORT
      LAYER met2 ;
        RECT 299.090 0.000 299.370 0.280 ;
    END
  END pad_pull_dir_11
  PIN pad_pull_dir_12
    DIRECTION OUTPUT ;
    USE SIGNAL ;
    ANTENNAGATEAREA 0.434700 ;
    ANTENNADIFFAREA 1.137600 ;
    PORT
      LAYER met2 ;
        RECT 300.930 0.000 301.210 0.280 ;
    END
  END pad_pull_dir_12
  PIN pad_pull_dir_13
    DIRECTION OUTPUT ;
    USE SIGNAL ;
    ANTENNAGATEAREA 0.434700 ;
    ANTENNADIFFAREA 1.137600 ;
    PORT
      LAYER met2 ;
        RECT 279.770 0.000 280.050 0.280 ;
    END
  END pad_pull_dir_13
  PIN pad_pull_dir_14
    DIRECTION OUTPUT ;
    USE SIGNAL ;
    ANTENNAGATEAREA 0.434700 ;
    ANTENNADIFFAREA 1.137600 ;
    PORT
      LAYER met2 ;
        RECT 292.650 0.000 292.930 0.280 ;
    END
  END pad_pull_dir_14
  PIN pad_pull_dir_15
    DIRECTION OUTPUT ;
    USE SIGNAL ;
    ANTENNAGATEAREA 0.434700 ;
    ANTENNADIFFAREA 1.137600 ;
    PORT
      LAYER met2 ;
        RECT 294.490 0.000 294.770 0.280 ;
    END
  END pad_pull_dir_15
  PIN pad_pull_dir_16
    DIRECTION OUTPUT ;
    USE SIGNAL ;
    ANTENNAGATEAREA 0.434700 ;
    ANTENNADIFFAREA 1.137600 ;
    PORT
      LAYER met2 ;
        RECT 296.330 0.000 296.610 0.280 ;
    END
  END pad_pull_dir_16
  PIN pad_pull_dir_17
    DIRECTION OUTPUT ;
    USE SIGNAL ;
    ANTENNAGATEAREA 0.434700 ;
    ANTENNADIFFAREA 1.137600 ;
    PORT
      LAYER met2 ;
        RECT 300.010 0.000 300.290 0.280 ;
    END
  END pad_pull_dir_17
  PIN pad_pull_dir_18
    DIRECTION OUTPUT ;
    USE SIGNAL ;
    ANTENNAGATEAREA 0.434700 ;
    ANTENNADIFFAREA 1.137600 ;
    PORT
      LAYER met2 ;
        RECT 283.450 0.000 283.730 0.280 ;
    END
  END pad_pull_dir_18
  PIN pad_pull_dir_19
    DIRECTION OUTPUT ;
    USE SIGNAL ;
    ANTENNAGATEAREA 0.434700 ;
    ANTENNADIFFAREA 1.137600 ;
    PORT
      LAYER met2 ;
        RECT 282.530 0.000 282.810 0.280 ;
    END
  END pad_pull_dir_19
  PIN pad_pull_dir_2
    DIRECTION OUTPUT ;
    USE SIGNAL ;
    ANTENNAGATEAREA 0.434700 ;
    ANTENNADIFFAREA 1.137600 ;
    PORT
      LAYER met2 ;
        RECT 303.690 0.000 303.970 0.280 ;
    END
  END pad_pull_dir_2
  PIN pad_pull_dir_20
    DIRECTION OUTPUT ;
    USE SIGNAL ;
    ANTENNAGATEAREA 0.434700 ;
    ANTENNADIFFAREA 1.137600 ;
    PORT
      LAYER met2 ;
        RECT 291.730 0.000 292.010 0.280 ;
    END
  END pad_pull_dir_20
  PIN pad_pull_dir_21
    DIRECTION OUTPUT ;
    USE SIGNAL ;
    ANTENNAGATEAREA 0.434700 ;
    ANTENNADIFFAREA 1.137600 ;
    PORT
      LAYER met2 ;
        RECT 289.890 0.000 290.170 0.280 ;
    END
  END pad_pull_dir_21
  PIN pad_pull_dir_22
    DIRECTION OUTPUT ;
    USE SIGNAL ;
    ANTENNAGATEAREA 0.434700 ;
    ANTENNADIFFAREA 1.137600 ;
    PORT
      LAYER met2 ;
        RECT 278.850 0.000 279.130 0.280 ;
    END
  END pad_pull_dir_22
  PIN pad_pull_dir_23
    DIRECTION OUTPUT ;
    USE SIGNAL ;
    ANTENNAGATEAREA 0.434700 ;
    ANTENNADIFFAREA 1.137600 ;
    PORT
      LAYER met2 ;
        RECT 313.810 0.000 314.090 0.280 ;
    END
  END pad_pull_dir_23
  PIN pad_pull_dir_24
    DIRECTION OUTPUT ;
    USE SIGNAL ;
    ANTENNAGATEAREA 0.434700 ;
    ANTENNADIFFAREA 1.137600 ;
    PORT
      LAYER met2 ;
        RECT 288.970 0.000 289.250 0.280 ;
    END
  END pad_pull_dir_24
  PIN pad_pull_dir_25
    DIRECTION OUTPUT ;
    USE SIGNAL ;
    ANTENNAGATEAREA 0.434700 ;
    ANTENNADIFFAREA 1.137600 ;
    PORT
      LAYER met2 ;
        RECT 306.450 0.000 306.730 0.280 ;
    END
  END pad_pull_dir_25
  PIN pad_pull_dir_26
    DIRECTION OUTPUT ;
    USE SIGNAL ;
    ANTENNAGATEAREA 0.434700 ;
    ANTENNADIFFAREA 1.137600 ;
    PORT
      LAYER met2 ;
        RECT 277.010 0.000 277.290 0.280 ;
    END
  END pad_pull_dir_26
  PIN pad_pull_dir_27
    DIRECTION OUTPUT ;
    USE SIGNAL ;
    ANTENNAGATEAREA 0.434700 ;
    ANTENNADIFFAREA 1.137600 ;
    PORT
      LAYER met2 ;
        RECT 301.850 0.000 302.130 0.280 ;
    END
  END pad_pull_dir_27
  PIN pad_pull_dir_28
    DIRECTION OUTPUT ;
    USE SIGNAL ;
    ANTENNAGATEAREA 0.434700 ;
    ANTENNADIFFAREA 1.137600 ;
    PORT
      LAYER met2 ;
        RECT 288.050 0.000 288.330 0.280 ;
    END
  END pad_pull_dir_28
  PIN pad_pull_dir_29
    DIRECTION OUTPUT ;
    USE SIGNAL ;
    ANTENNAGATEAREA 0.434700 ;
    ANTENNADIFFAREA 1.137600 ;
    PORT
      LAYER met2 ;
        RECT 277.930 0.000 278.210 0.280 ;
    END
  END pad_pull_dir_29
  PIN pad_pull_dir_3
    DIRECTION OUTPUT ;
    USE SIGNAL ;
    ANTENNAGATEAREA 0.434700 ;
    ANTENNADIFFAREA 1.137600 ;
    PORT
      LAYER met2 ;
        RECT 275.170 0.000 275.450 0.280 ;
    END
  END pad_pull_dir_3
  PIN pad_pull_dir_30
    DIRECTION OUTPUT ;
    USE SIGNAL ;
    ANTENNAGATEAREA 0.434700 ;
    ANTENNADIFFAREA 1.137600 ;
    PORT
      LAYER met2 ;
        RECT 297.250 0.000 297.530 0.280 ;
    END
  END pad_pull_dir_30
  PIN pad_pull_dir_31
    DIRECTION OUTPUT ;
    USE SIGNAL ;
    ANTENNAGATEAREA 0.434700 ;
    ANTENNADIFFAREA 1.137600 ;
    PORT
      LAYER met2 ;
        RECT 317.490 0.000 317.770 0.280 ;
    END
  END pad_pull_dir_31
  PIN pad_pull_dir_4
    DIRECTION OUTPUT ;
    USE SIGNAL ;
    ANTENNAGATEAREA 0.434700 ;
    ANTENNADIFFAREA 1.137600 ;
    PORT
      LAYER met2 ;
        RECT 295.410 0.000 295.690 0.280 ;
    END
  END pad_pull_dir_4
  PIN pad_pull_dir_5
    DIRECTION OUTPUT ;
    USE SIGNAL ;
    ANTENNAGATEAREA 0.434700 ;
    ANTENNADIFFAREA 1.137600 ;
    PORT
      LAYER met2 ;
        RECT 286.210 0.000 286.490 0.280 ;
    END
  END pad_pull_dir_5
  PIN pad_pull_dir_6
    DIRECTION OUTPUT ;
    USE SIGNAL ;
    ANTENNAGATEAREA 0.434700 ;
    ANTENNADIFFAREA 1.137600 ;
    PORT
      LAYER met2 ;
        RECT 280.690 0.000 280.970 0.280 ;
    END
  END pad_pull_dir_6
  PIN pad_pull_dir_7
    DIRECTION OUTPUT ;
    USE SIGNAL ;
    ANTENNAGATEAREA 0.434700 ;
    ANTENNADIFFAREA 1.137600 ;
    PORT
      LAYER met2 ;
        RECT 293.570 0.000 293.850 0.280 ;
    END
  END pad_pull_dir_7
  PIN pad_pull_dir_8
    DIRECTION OUTPUT ;
    USE SIGNAL ;
    ANTENNAGATEAREA 0.434700 ;
    ANTENNADIFFAREA 1.137600 ;
    PORT
      LAYER met2 ;
        RECT 285.290 0.000 285.570 0.280 ;
    END
  END pad_pull_dir_8
  PIN pad_pull_dir_9
    DIRECTION OUTPUT ;
    USE SIGNAL ;
    ANTENNAGATEAREA 0.434700 ;
    ANTENNADIFFAREA 1.137600 ;
    PORT
      LAYER met2 ;
        RECT 304.610 0.000 304.890 0.280 ;
    END
  END pad_pull_dir_9
  PIN pad_pull_en_0
    DIRECTION OUTPUT ;
    USE SIGNAL ;
    ANTENNAGATEAREA 0.434700 ;
    ANTENNADIFFAREA 1.137600 ;
    PORT
      LAYER met3 ;
        RECT 367.665 112.920 368.265 113.520 ;
    END
  END pad_pull_en_0
  PIN pad_pull_en_1
    DIRECTION OUTPUT ;
    USE SIGNAL ;
    ANTENNAGATEAREA 0.434700 ;
    ANTENNADIFFAREA 1.137600 ;
    PORT
      LAYER met3 ;
        RECT 367.665 54.440 368.265 55.040 ;
    END
  END pad_pull_en_1
  PIN pad_pull_en_10
    DIRECTION OUTPUT ;
    USE SIGNAL ;
    ANTENNAGATEAREA 0.434700 ;
    ANTENNADIFFAREA 1.137600 ;
    PORT
      LAYER met3 ;
        RECT 367.665 72.120 368.265 72.720 ;
    END
  END pad_pull_en_10
  PIN pad_pull_en_11
    DIRECTION OUTPUT ;
    USE SIGNAL ;
    ANTENNAGATEAREA 0.434700 ;
    ANTENNADIFFAREA 1.137600 ;
    PORT
      LAYER met3 ;
        RECT 367.665 83.000 368.265 83.600 ;
    END
  END pad_pull_en_11
  PIN pad_pull_en_12
    DIRECTION OUTPUT ;
    USE SIGNAL ;
    ANTENNAGATEAREA 0.434700 ;
    ANTENNADIFFAREA 1.137600 ;
    PORT
      LAYER met3 ;
        RECT 367.665 110.200 368.265 110.800 ;
    END
  END pad_pull_en_12
  PIN pad_pull_en_13
    DIRECTION OUTPUT ;
    USE SIGNAL ;
    ANTENNAGATEAREA 0.434700 ;
    ANTENNADIFFAREA 1.137600 ;
    PORT
      LAYER met3 ;
        RECT 367.665 92.520 368.265 93.120 ;
    END
  END pad_pull_en_13
  PIN pad_pull_en_14
    DIRECTION OUTPUT ;
    USE SIGNAL ;
    ANTENNAGATEAREA 0.434700 ;
    ANTENNADIFFAREA 1.137600 ;
    PORT
      LAYER met3 ;
        RECT 367.665 96.600 368.265 97.200 ;
    END
  END pad_pull_en_14
  PIN pad_pull_en_15
    DIRECTION OUTPUT ;
    USE SIGNAL ;
    ANTENNAGATEAREA 0.434700 ;
    ANTENNADIFFAREA 1.137600 ;
    PORT
      LAYER met3 ;
        RECT 367.665 55.800 368.265 56.400 ;
    END
  END pad_pull_en_15
  PIN pad_pull_en_16
    DIRECTION OUTPUT ;
    USE SIGNAL ;
    ANTENNAGATEAREA 0.434700 ;
    ANTENNADIFFAREA 1.137600 ;
    PORT
      LAYER met3 ;
        RECT 367.665 84.360 368.265 84.960 ;
    END
  END pad_pull_en_16
  PIN pad_pull_en_17
    DIRECTION OUTPUT ;
    USE SIGNAL ;
    ANTENNAGATEAREA 0.434700 ;
    ANTENNADIFFAREA 1.137600 ;
    PORT
      LAYER met3 ;
        RECT 367.665 77.560 368.265 78.160 ;
    END
  END pad_pull_en_17
  PIN pad_pull_en_18
    DIRECTION OUTPUT ;
    USE SIGNAL ;
    ANTENNAGATEAREA 0.434700 ;
    ANTENNADIFFAREA 1.137600 ;
    PORT
      LAYER met3 ;
        RECT 367.665 50.360 368.265 50.960 ;
    END
  END pad_pull_en_18
  PIN pad_pull_en_19
    DIRECTION OUTPUT ;
    USE SIGNAL ;
    ANTENNAGATEAREA 0.434700 ;
    ANTENNADIFFAREA 1.137600 ;
    PORT
      LAYER met3 ;
        RECT 367.665 91.160 368.265 91.760 ;
    END
  END pad_pull_en_19
  PIN pad_pull_en_2
    DIRECTION OUTPUT ;
    USE SIGNAL ;
    ANTENNAGATEAREA 0.434700 ;
    ANTENNADIFFAREA 1.137600 ;
    PORT
      LAYER met3 ;
        RECT 367.665 99.320 368.265 99.920 ;
    END
  END pad_pull_en_2
  PIN pad_pull_en_20
    DIRECTION OUTPUT ;
    USE SIGNAL ;
    ANTENNAGATEAREA 0.434700 ;
    ANTENNADIFFAREA 1.137600 ;
    PORT
      LAYER met3 ;
        RECT 367.665 68.040 368.265 68.640 ;
    END
  END pad_pull_en_20
  PIN pad_pull_en_21
    DIRECTION OUTPUT ;
    USE SIGNAL ;
    ANTENNAGATEAREA 0.434700 ;
    ANTENNADIFFAREA 1.137600 ;
    PORT
      LAYER met3 ;
        RECT 367.665 32.680 368.265 33.280 ;
    END
  END pad_pull_en_21
  PIN pad_pull_en_22
    DIRECTION OUTPUT ;
    USE SIGNAL ;
    ANTENNAGATEAREA 0.434700 ;
    ANTENNADIFFAREA 1.137600 ;
    PORT
      LAYER met3 ;
        RECT 367.665 43.560 368.265 44.160 ;
    END
  END pad_pull_en_22
  PIN pad_pull_en_23
    DIRECTION OUTPUT ;
    USE SIGNAL ;
    ANTENNAGATEAREA 0.434700 ;
    ANTENNADIFFAREA 1.137600 ;
    PORT
      LAYER met3 ;
        RECT 367.665 70.760 368.265 71.360 ;
    END
  END pad_pull_en_23
  PIN pad_pull_en_24
    DIRECTION OUTPUT ;
    USE SIGNAL ;
    ANTENNAGATEAREA 0.434700 ;
    ANTENNADIFFAREA 1.137600 ;
    PORT
      LAYER met3 ;
        RECT 367.665 69.400 368.265 70.000 ;
    END
  END pad_pull_en_24
  PIN pad_pull_en_25
    DIRECTION OUTPUT ;
    USE SIGNAL ;
    ANTENNAGATEAREA 0.434700 ;
    ANTENNADIFFAREA 1.137600 ;
    PORT
      LAYER met3 ;
        RECT 367.665 28.600 368.265 29.200 ;
    END
  END pad_pull_en_25
  PIN pad_pull_en_26
    DIRECTION OUTPUT ;
    USE SIGNAL ;
    ANTENNAGATEAREA 0.434700 ;
    ANTENNADIFFAREA 1.137600 ;
    PORT
      LAYER met3 ;
        RECT 367.665 81.640 368.265 82.240 ;
    END
  END pad_pull_en_26
  PIN pad_pull_en_27
    DIRECTION OUTPUT ;
    USE SIGNAL ;
    ANTENNAGATEAREA 0.434700 ;
    ANTENNADIFFAREA 1.137600 ;
    PORT
      LAYER met3 ;
        RECT 367.665 95.240 368.265 95.840 ;
    END
  END pad_pull_en_27
  PIN pad_pull_en_28
    DIRECTION OUTPUT ;
    USE SIGNAL ;
    ANTENNAGATEAREA 0.434700 ;
    ANTENNADIFFAREA 1.137600 ;
    PORT
      LAYER met3 ;
        RECT 367.665 63.960 368.265 64.560 ;
    END
  END pad_pull_en_28
  PIN pad_pull_en_29
    DIRECTION OUTPUT ;
    USE SIGNAL ;
    ANTENNAGATEAREA 0.434700 ;
    ANTENNADIFFAREA 1.137600 ;
    PORT
      LAYER met3 ;
        RECT 367.665 49.000 368.265 49.600 ;
    END
  END pad_pull_en_29
  PIN pad_pull_en_3
    DIRECTION OUTPUT ;
    USE SIGNAL ;
    ANTENNAGATEAREA 0.434700 ;
    ANTENNADIFFAREA 1.137600 ;
    PORT
      LAYER met3 ;
        RECT 367.665 87.080 368.265 87.680 ;
    END
  END pad_pull_en_3
  PIN pad_pull_en_30
    DIRECTION OUTPUT ;
    USE SIGNAL ;
    ANTENNAGATEAREA 0.434700 ;
    ANTENNADIFFAREA 1.137600 ;
    PORT
      LAYER met3 ;
        RECT 367.665 65.320 368.265 65.920 ;
    END
  END pad_pull_en_30
  PIN pad_pull_en_31
    DIRECTION OUTPUT ;
    USE SIGNAL ;
    ANTENNAGATEAREA 0.434700 ;
    ANTENNADIFFAREA 1.137600 ;
    PORT
      LAYER met3 ;
        RECT 367.665 80.280 368.265 80.880 ;
    END
  END pad_pull_en_31
  PIN pad_pull_en_4
    DIRECTION OUTPUT ;
    USE SIGNAL ;
    ANTENNAGATEAREA 0.434700 ;
    ANTENNADIFFAREA 1.137600 ;
    PORT
      LAYER met3 ;
        RECT 367.665 27.240 368.265 27.840 ;
    END
  END pad_pull_en_4
  PIN pad_pull_en_5
    DIRECTION OUTPUT ;
    USE SIGNAL ;
    ANTENNAGATEAREA 0.434700 ;
    ANTENNADIFFAREA 1.137600 ;
    PORT
      LAYER met3 ;
        RECT 367.665 78.920 368.265 79.520 ;
    END
  END pad_pull_en_5
  PIN pad_pull_en_6
    DIRECTION OUTPUT ;
    USE SIGNAL ;
    ANTENNAGATEAREA 0.434700 ;
    ANTENNADIFFAREA 1.137600 ;
    PORT
      LAYER met3 ;
        RECT 367.665 107.480 368.265 108.080 ;
    END
  END pad_pull_en_6
  PIN pad_pull_en_7
    DIRECTION OUTPUT ;
    USE SIGNAL ;
    ANTENNAGATEAREA 0.434700 ;
    ANTENNADIFFAREA 1.137600 ;
    PORT
      LAYER met3 ;
        RECT 367.665 93.880 368.265 94.480 ;
    END
  END pad_pull_en_7
  PIN pad_pull_en_8
    DIRECTION OUTPUT ;
    USE SIGNAL ;
    ANTENNAGATEAREA 0.434700 ;
    ANTENNADIFFAREA 1.137600 ;
    PORT
      LAYER met3 ;
        RECT 367.665 42.200 368.265 42.800 ;
    END
  END pad_pull_en_8
  PIN pad_pull_en_9
    DIRECTION OUTPUT ;
    USE SIGNAL ;
    ANTENNAGATEAREA 0.434700 ;
    ANTENNADIFFAREA 1.137600 ;
    PORT
      LAYER met3 ;
        RECT 367.665 89.800 368.265 90.400 ;
    END
  END pad_pull_en_9
  PIN pad_schmitt_0
    DIRECTION OUTPUT ;
    USE SIGNAL ;
    ANTENNAGATEAREA 0.434700 ;
    ANTENNADIFFAREA 1.137600 ;
    PORT
      LAYER met3 ;
        RECT 367.665 115.640 368.265 116.240 ;
    END
  END pad_schmitt_0
  PIN pad_schmitt_1
    DIRECTION OUTPUT ;
    USE SIGNAL ;
    ANTENNAGATEAREA 0.434700 ;
    ANTENNADIFFAREA 1.137600 ;
    PORT
      LAYER met3 ;
        RECT 367.665 57.160 368.265 57.760 ;
    END
  END pad_schmitt_1
  PIN pad_schmitt_10
    DIRECTION OUTPUT ;
    USE SIGNAL ;
    ANTENNAGATEAREA 0.434700 ;
    ANTENNADIFFAREA 1.137600 ;
    PORT
      LAYER met3 ;
        RECT 367.665 121.080 368.265 121.680 ;
    END
  END pad_schmitt_10
  PIN pad_schmitt_11
    DIRECTION OUTPUT ;
    USE SIGNAL ;
    ANTENNAGATEAREA 0.434700 ;
    ANTENNADIFFAREA 1.137600 ;
    PORT
      LAYER met3 ;
        RECT 367.665 10.920 368.265 11.520 ;
    END
  END pad_schmitt_11
  PIN pad_schmitt_12
    DIRECTION OUTPUT ;
    USE SIGNAL ;
    ANTENNAGATEAREA 0.434700 ;
    ANTENNADIFFAREA 1.137600 ;
    PORT
      LAYER met3 ;
        RECT 367.665 123.800 368.265 124.400 ;
    END
  END pad_schmitt_12
  PIN pad_schmitt_13
    DIRECTION OUTPUT ;
    USE SIGNAL ;
    ANTENNAGATEAREA 0.434700 ;
    ANTENNADIFFAREA 1.137600 ;
    PORT
      LAYER met3 ;
        RECT 367.665 104.760 368.265 105.360 ;
    END
  END pad_schmitt_13
  PIN pad_schmitt_14
    DIRECTION OUTPUT ;
    USE SIGNAL ;
    ANTENNAGATEAREA 0.434700 ;
    ANTENNADIFFAREA 1.137600 ;
    PORT
      LAYER met3 ;
        RECT 367.665 35.400 368.265 36.000 ;
    END
  END pad_schmitt_14
  PIN pad_schmitt_15
    DIRECTION OUTPUT ;
    USE SIGNAL ;
    ANTENNAGATEAREA 0.434700 ;
    ANTENNADIFFAREA 1.137600 ;
    PORT
      LAYER met3 ;
        RECT 367.665 118.360 368.265 118.960 ;
    END
  END pad_schmitt_15
  PIN pad_schmitt_16
    DIRECTION OUTPUT ;
    USE SIGNAL ;
    ANTENNAGATEAREA 0.434700 ;
    ANTENNADIFFAREA 1.137600 ;
    PORT
      LAYER met3 ;
        RECT 367.665 142.840 368.265 143.440 ;
    END
  END pad_schmitt_16
  PIN pad_schmitt_17
    DIRECTION OUTPUT ;
    USE SIGNAL ;
    ANTENNAGATEAREA 0.434700 ;
    ANTENNADIFFAREA 1.137600 ;
    PORT
      LAYER met3 ;
        RECT 367.665 125.160 368.265 125.760 ;
    END
  END pad_schmitt_17
  PIN pad_schmitt_18
    DIRECTION OUTPUT ;
    USE SIGNAL ;
    ANTENNAGATEAREA 0.434700 ;
    ANTENNADIFFAREA 1.137600 ;
    PORT
      LAYER met3 ;
        RECT 367.665 137.400 368.265 138.000 ;
    END
  END pad_schmitt_18
  PIN pad_schmitt_19
    DIRECTION OUTPUT ;
    USE SIGNAL ;
    ANTENNAGATEAREA 0.434700 ;
    ANTENNADIFFAREA 1.137600 ;
    PORT
      LAYER met3 ;
        RECT 367.665 46.280 368.265 46.880 ;
    END
  END pad_schmitt_19
  PIN pad_schmitt_2
    DIRECTION OUTPUT ;
    USE SIGNAL ;
    ANTENNAGATEAREA 0.434700 ;
    ANTENNADIFFAREA 1.137600 ;
    PORT
      LAYER met3 ;
        RECT 367.665 62.600 368.265 63.200 ;
    END
  END pad_schmitt_2
  PIN pad_schmitt_20
    DIRECTION OUTPUT ;
    USE SIGNAL ;
    ANTENNAGATEAREA 0.434700 ;
    ANTENNADIFFAREA 1.137600 ;
    PORT
      LAYER met3 ;
        RECT 367.665 126.520 368.265 127.120 ;
    END
  END pad_schmitt_20
  PIN pad_schmitt_21
    DIRECTION OUTPUT ;
    USE SIGNAL ;
    ANTENNAGATEAREA 0.434700 ;
    ANTENNADIFFAREA 1.137600 ;
    PORT
      LAYER met3 ;
        RECT 367.665 39.480 368.265 40.080 ;
    END
  END pad_schmitt_21
  PIN pad_schmitt_22
    DIRECTION OUTPUT ;
    USE SIGNAL ;
    ANTENNAGATEAREA 0.434700 ;
    ANTENNADIFFAREA 1.137600 ;
    PORT
      LAYER met3 ;
        RECT 367.665 127.880 368.265 128.480 ;
    END
  END pad_schmitt_22
  PIN pad_schmitt_23
    DIRECTION OUTPUT ;
    USE SIGNAL ;
    ANTENNAGATEAREA 0.434700 ;
    ANTENNADIFFAREA 1.137600 ;
    PORT
      LAYER met3 ;
        RECT 367.665 106.120 368.265 106.720 ;
    END
  END pad_schmitt_23
  PIN pad_schmitt_24
    DIRECTION OUTPUT ;
    USE SIGNAL ;
    ANTENNAGATEAREA 0.434700 ;
    ANTENNADIFFAREA 1.137600 ;
    PORT
      LAYER met3 ;
        RECT 367.665 103.400 368.265 104.000 ;
    END
  END pad_schmitt_24
  PIN pad_schmitt_25
    DIRECTION OUTPUT ;
    USE SIGNAL ;
    ANTENNAGATEAREA 0.434700 ;
    ANTENNADIFFAREA 1.137600 ;
    PORT
      LAYER met3 ;
        RECT 367.665 130.600 368.265 131.200 ;
    END
  END pad_schmitt_25
  PIN pad_schmitt_26
    DIRECTION OUTPUT ;
    USE SIGNAL ;
    ANTENNAGATEAREA 0.434700 ;
    ANTENNADIFFAREA 1.137600 ;
    PORT
      LAYER met3 ;
        RECT 367.665 97.960 368.265 98.560 ;
    END
  END pad_schmitt_26
  PIN pad_schmitt_27
    DIRECTION OUTPUT ;
    USE SIGNAL ;
    ANTENNAGATEAREA 0.434700 ;
    ANTENNADIFFAREA 1.137600 ;
    PORT
      LAYER met3 ;
        RECT 367.665 131.960 368.265 132.560 ;
    END
  END pad_schmitt_27
  PIN pad_schmitt_28
    DIRECTION OUTPUT ;
    USE SIGNAL ;
    ANTENNAGATEAREA 0.434700 ;
    ANTENNADIFFAREA 1.137600 ;
    PORT
      LAYER met3 ;
        RECT 367.665 136.040 368.265 136.640 ;
    END
  END pad_schmitt_28
  PIN pad_schmitt_29
    DIRECTION OUTPUT ;
    USE SIGNAL ;
    ANTENNAGATEAREA 0.434700 ;
    ANTENNADIFFAREA 1.137600 ;
    PORT
      LAYER met3 ;
        RECT 367.665 53.080 368.265 53.680 ;
    END
  END pad_schmitt_29
  PIN pad_schmitt_3
    DIRECTION OUTPUT ;
    USE SIGNAL ;
    ANTENNAGATEAREA 0.434700 ;
    ANTENNADIFFAREA 1.137600 ;
    PORT
      LAYER met3 ;
        RECT 367.665 38.120 368.265 38.720 ;
    END
  END pad_schmitt_3
  PIN pad_schmitt_30
    DIRECTION OUTPUT ;
    USE SIGNAL ;
    ANTENNAGATEAREA 0.434700 ;
    ANTENNADIFFAREA 1.137600 ;
    PORT
      LAYER met3 ;
        RECT 367.665 74.840 368.265 75.440 ;
    END
  END pad_schmitt_30
  PIN pad_schmitt_31
    DIRECTION OUTPUT ;
    USE SIGNAL ;
    ANTENNAGATEAREA 0.434700 ;
    ANTENNADIFFAREA 1.137600 ;
    PORT
      LAYER met3 ;
        RECT 367.665 23.160 368.265 23.760 ;
    END
  END pad_schmitt_31
  PIN pad_schmitt_4
    DIRECTION OUTPUT ;
    USE SIGNAL ;
    ANTENNAGATEAREA 0.434700 ;
    ANTENNADIFFAREA 1.137600 ;
    PORT
      LAYER met3 ;
        RECT 367.665 129.240 368.265 129.840 ;
    END
  END pad_schmitt_4
  PIN pad_schmitt_5
    DIRECTION OUTPUT ;
    USE SIGNAL ;
    ANTENNAGATEAREA 0.434700 ;
    ANTENNADIFFAREA 1.137600 ;
    PORT
      LAYER met3 ;
        RECT 367.665 114.280 368.265 114.880 ;
    END
  END pad_schmitt_5
  PIN pad_schmitt_6
    DIRECTION OUTPUT ;
    USE SIGNAL ;
    ANTENNAGATEAREA 0.434700 ;
    ANTENNADIFFAREA 1.137600 ;
    PORT
      LAYER met3 ;
        RECT 367.665 24.520 368.265 25.120 ;
    END
  END pad_schmitt_6
  PIN pad_schmitt_7
    DIRECTION OUTPUT ;
    USE SIGNAL ;
    ANTENNAGATEAREA 0.434700 ;
    ANTENNADIFFAREA 1.137600 ;
    PORT
      LAYER met3 ;
        RECT 367.665 76.200 368.265 76.800 ;
    END
  END pad_schmitt_7
  PIN pad_schmitt_8
    DIRECTION OUTPUT ;
    USE SIGNAL ;
    ANTENNAGATEAREA 0.434700 ;
    ANTENNADIFFAREA 1.137600 ;
    PORT
      LAYER met3 ;
        RECT 367.665 133.320 368.265 133.920 ;
    END
  END pad_schmitt_8
  PIN pad_schmitt_9
    DIRECTION OUTPUT ;
    USE SIGNAL ;
    ANTENNAGATEAREA 0.434700 ;
    ANTENNADIFFAREA 1.137600 ;
    PORT
      LAYER met3 ;
        RECT 367.665 138.760 368.265 139.360 ;
    END
  END pad_schmitt_9
  PIN pad_slew_0
    DIRECTION OUTPUT ;
    USE SIGNAL ;
    ANTENNAGATEAREA 0.434700 ;
    ANTENNADIFFAREA 1.137600 ;
    PORT
      LAYER met3 ;
        RECT 367.665 197.240 368.265 197.840 ;
    END
  END pad_slew_0
  PIN pad_slew_1
    DIRECTION OUTPUT ;
    USE SIGNAL ;
    ANTENNAGATEAREA 0.434700 ;
    ANTENNADIFFAREA 1.137600 ;
    PORT
      LAYER met3 ;
        RECT 367.665 201.320 368.265 201.920 ;
    END
  END pad_slew_1
  PIN pad_slew_10
    DIRECTION OUTPUT ;
    USE SIGNAL ;
    ANTENNAGATEAREA 0.434700 ;
    ANTENNADIFFAREA 1.137600 ;
    PORT
      LAYER met3 ;
        RECT 367.665 259.800 368.265 260.400 ;
    END
  END pad_slew_10
  PIN pad_slew_11
    DIRECTION OUTPUT ;
    USE SIGNAL ;
    ANTENNAGATEAREA 0.434700 ;
    ANTENNADIFFAREA 1.137600 ;
    PORT
      LAYER met3 ;
        RECT 367.665 216.280 368.265 216.880 ;
    END
  END pad_slew_11
  PIN pad_slew_12
    DIRECTION OUTPUT ;
    USE SIGNAL ;
    ANTENNAGATEAREA 0.434700 ;
    ANTENNADIFFAREA 1.137600 ;
    PORT
      LAYER met3 ;
        RECT 367.665 244.840 368.265 245.440 ;
    END
  END pad_slew_12
  PIN pad_slew_13
    DIRECTION OUTPUT ;
    USE SIGNAL ;
    ANTENNAGATEAREA 0.434700 ;
    ANTENNADIFFAREA 1.137600 ;
    PORT
      LAYER met3 ;
        RECT 367.665 206.760 368.265 207.360 ;
    END
  END pad_slew_13
  PIN pad_slew_14
    DIRECTION OUTPUT ;
    USE SIGNAL ;
    ANTENNAGATEAREA 0.434700 ;
    ANTENNADIFFAREA 1.137600 ;
    PORT
      LAYER met3 ;
        RECT 367.665 198.600 368.265 199.200 ;
    END
  END pad_slew_14
  PIN pad_slew_15
    DIRECTION OUTPUT ;
    USE SIGNAL ;
    ANTENNAGATEAREA 0.434700 ;
    ANTENNADIFFAREA 1.137600 ;
    PORT
      LAYER met3 ;
        RECT 367.665 257.080 368.265 257.680 ;
    END
  END pad_slew_15
  PIN pad_slew_16
    DIRECTION OUTPUT ;
    USE SIGNAL ;
    ANTENNAGATEAREA 0.434700 ;
    ANTENNADIFFAREA 1.137600 ;
    PORT
      LAYER met3 ;
        RECT 367.665 205.400 368.265 206.000 ;
    END
  END pad_slew_16
  PIN pad_slew_17
    DIRECTION OUTPUT ;
    USE SIGNAL ;
    ANTENNAGATEAREA 0.434700 ;
    ANTENNADIFFAREA 1.137600 ;
    PORT
      LAYER met3 ;
        RECT 367.665 204.040 368.265 204.640 ;
    END
  END pad_slew_17
  PIN pad_slew_18
    DIRECTION OUTPUT ;
    USE SIGNAL ;
    ANTENNAGATEAREA 0.434700 ;
    ANTENNADIFFAREA 1.137600 ;
    PORT
      LAYER met3 ;
        RECT 367.665 194.520 368.265 195.120 ;
    END
  END pad_slew_18
  PIN pad_slew_19
    DIRECTION OUTPUT ;
    USE SIGNAL ;
    ANTENNAGATEAREA 0.434700 ;
    ANTENNADIFFAREA 1.137600 ;
    PORT
      LAYER met3 ;
        RECT 367.665 195.880 368.265 196.480 ;
    END
  END pad_slew_19
  PIN pad_slew_2
    DIRECTION OUTPUT ;
    USE SIGNAL ;
    ANTENNAGATEAREA 0.434700 ;
    ANTENNADIFFAREA 1.137600 ;
    PORT
      LAYER met3 ;
        RECT 367.665 233.960 368.265 234.560 ;
    END
  END pad_slew_2
  PIN pad_slew_20
    DIRECTION OUTPUT ;
    USE SIGNAL ;
    ANTENNAGATEAREA 0.434700 ;
    ANTENNADIFFAREA 1.137600 ;
    PORT
      LAYER met3 ;
        RECT 367.665 212.200 368.265 212.800 ;
    END
  END pad_slew_20
  PIN pad_slew_21
    DIRECTION OUTPUT ;
    USE SIGNAL ;
    ANTENNAGATEAREA 0.434700 ;
    ANTENNADIFFAREA 1.137600 ;
    PORT
      LAYER met3 ;
        RECT 367.665 263.880 368.265 264.480 ;
    END
  END pad_slew_21
  PIN pad_slew_22
    DIRECTION OUTPUT ;
    USE SIGNAL ;
    ANTENNAGATEAREA 0.434700 ;
    ANTENNADIFFAREA 1.137600 ;
    PORT
      LAYER met3 ;
        RECT 367.665 238.040 368.265 238.640 ;
    END
  END pad_slew_22
  PIN pad_slew_23
    DIRECTION OUTPUT ;
    USE SIGNAL ;
    ANTENNAGATEAREA 0.434700 ;
    ANTENNADIFFAREA 1.137600 ;
    PORT
      LAYER met3 ;
        RECT 367.665 199.960 368.265 200.560 ;
    END
  END pad_slew_23
  PIN pad_slew_24
    DIRECTION OUTPUT ;
    USE SIGNAL ;
    ANTENNAGATEAREA 0.434700 ;
    ANTENNADIFFAREA 1.137600 ;
    PORT
      LAYER met3 ;
        RECT 367.665 213.560 368.265 214.160 ;
    END
  END pad_slew_24
  PIN pad_slew_25
    DIRECTION OUTPUT ;
    USE SIGNAL ;
    ANTENNAGATEAREA 0.434700 ;
    ANTENNADIFFAREA 1.137600 ;
    PORT
      LAYER met3 ;
        RECT 367.665 202.680 368.265 203.280 ;
    END
  END pad_slew_25
  PIN pad_slew_26
    DIRECTION OUTPUT ;
    USE SIGNAL ;
    ANTENNAGATEAREA 0.434700 ;
    ANTENNADIFFAREA 1.137600 ;
    PORT
      LAYER met3 ;
        RECT 367.665 239.400 368.265 240.000 ;
    END
  END pad_slew_26
  PIN pad_slew_27
    DIRECTION OUTPUT ;
    USE SIGNAL ;
    ANTENNAGATEAREA 0.434700 ;
    ANTENNADIFFAREA 1.137600 ;
    PORT
      LAYER met3 ;
        RECT 367.665 267.960 368.265 268.560 ;
    END
  END pad_slew_27
  PIN pad_slew_28
    DIRECTION OUTPUT ;
    USE SIGNAL ;
    ANTENNAGATEAREA 0.434700 ;
    ANTENNADIFFAREA 1.137600 ;
    PORT
      LAYER met3 ;
        RECT 367.665 265.240 368.265 265.840 ;
    END
  END pad_slew_28
  PIN pad_slew_29
    DIRECTION OUTPUT ;
    USE SIGNAL ;
    ANTENNAGATEAREA 0.434700 ;
    ANTENNADIFFAREA 1.137600 ;
    PORT
      LAYER met3 ;
        RECT 367.665 247.560 368.265 248.160 ;
    END
  END pad_slew_29
  PIN pad_slew_3
    DIRECTION OUTPUT ;
    USE SIGNAL ;
    ANTENNAGATEAREA 0.434700 ;
    ANTENNADIFFAREA 1.137600 ;
    PORT
      LAYER met3 ;
        RECT 367.665 219.000 368.265 219.600 ;
    END
  END pad_slew_3
  PIN pad_slew_30
    DIRECTION OUTPUT ;
    USE SIGNAL ;
    ANTENNAGATEAREA 0.434700 ;
    ANTENNADIFFAREA 1.137600 ;
    PORT
      LAYER met3 ;
        RECT 367.665 220.360 368.265 220.960 ;
    END
  END pad_slew_30
  PIN pad_slew_31
    DIRECTION OUTPUT ;
    USE SIGNAL ;
    ANTENNAGATEAREA 0.434700 ;
    ANTENNADIFFAREA 1.137600 ;
    PORT
      LAYER met3 ;
        RECT 367.665 254.360 368.265 254.960 ;
    END
  END pad_slew_31
  PIN pad_slew_4
    DIRECTION OUTPUT ;
    USE SIGNAL ;
    ANTENNAGATEAREA 0.434700 ;
    ANTENNADIFFAREA 1.137600 ;
    PORT
      LAYER met3 ;
        RECT 367.665 272.040 368.265 272.640 ;
    END
  END pad_slew_4
  PIN pad_slew_5
    DIRECTION OUTPUT ;
    USE SIGNAL ;
    ANTENNAGATEAREA 0.434700 ;
    ANTENNADIFFAREA 1.137600 ;
    PORT
      LAYER met3 ;
        RECT 367.665 240.760 368.265 241.360 ;
    END
  END pad_slew_5
  PIN pad_slew_6
    DIRECTION OUTPUT ;
    USE SIGNAL ;
    ANTENNAGATEAREA 0.434700 ;
    ANTENNADIFFAREA 1.137600 ;
    PORT
      LAYER met3 ;
        RECT 367.665 209.480 368.265 210.080 ;
    END
  END pad_slew_6
  PIN pad_slew_7
    DIRECTION OUTPUT ;
    USE SIGNAL ;
    ANTENNAGATEAREA 0.434700 ;
    ANTENNADIFFAREA 1.137600 ;
    PORT
      LAYER met3 ;
        RECT 367.665 217.640 368.265 218.240 ;
    END
  END pad_slew_7
  PIN pad_slew_8
    DIRECTION OUTPUT ;
    USE SIGNAL ;
    ANTENNAGATEAREA 0.434700 ;
    ANTENNADIFFAREA 1.137600 ;
    PORT
      LAYER met3 ;
        RECT 367.665 225.800 368.265 226.400 ;
    END
  END pad_slew_8
  PIN pad_slew_9
    DIRECTION OUTPUT ;
    USE SIGNAL ;
    ANTENNAGATEAREA 0.434700 ;
    ANTENNADIFFAREA 1.137600 ;
    PORT
      LAYER met3 ;
        RECT 367.665 255.720 368.265 256.320 ;
    END
  END pad_slew_9
  PIN periph_oe_0
    DIRECTION INPUT ;
    USE SIGNAL ;
    ANTENNAGATEAREA 0.647700 ;
    ANTENNADIFFAREA 0.434700 ;
    PORT
      LAYER met3 ;
        RECT 367.665 34.040 368.265 34.640 ;
    END
  END periph_oe_0
  PIN periph_oe_1
    DIRECTION INPUT ;
    USE SIGNAL ;
    ANTENNAGATEAREA 0.647700 ;
    ANTENNADIFFAREA 0.434700 ;
    PORT
      LAYER met3 ;
        RECT 367.665 175.480 368.265 176.080 ;
    END
  END periph_oe_1
  PIN periph_oe_10
    DIRECTION INPUT ;
    USE SIGNAL ;
    ANTENNAGATEAREA 0.647700 ;
    ANTENNADIFFAREA 0.434700 ;
    PORT
      LAYER met3 ;
        RECT 367.665 61.240 368.265 61.840 ;
    END
  END periph_oe_10
  PIN periph_oe_11
    DIRECTION INPUT ;
    USE SIGNAL ;
    ANTENNAGATEAREA 0.647700 ;
    ANTENNADIFFAREA 0.434700 ;
    PORT
      LAYER met3 ;
        RECT 367.665 102.040 368.265 102.640 ;
    END
  END periph_oe_11
  PIN periph_oe_12
    DIRECTION INPUT ;
    USE SIGNAL ;
    ANTENNAGATEAREA 0.647700 ;
    ANTENNADIFFAREA 0.434700 ;
    PORT
      LAYER met3 ;
        RECT 367.665 44.920 368.265 45.520 ;
    END
  END periph_oe_12
  PIN periph_oe_13
    DIRECTION INPUT ;
    USE SIGNAL ;
    ANTENNAGATEAREA 0.647700 ;
    ANTENNADIFFAREA 0.434700 ;
    PORT
      LAYER met3 ;
        RECT 367.665 140.120 368.265 140.720 ;
    END
  END periph_oe_13
  PIN periph_oe_14
    DIRECTION INPUT ;
    USE SIGNAL ;
    ANTENNAGATEAREA 0.647700 ;
    ANTENNADIFFAREA 0.434700 ;
    PORT
      LAYER met3 ;
        RECT 367.665 31.320 368.265 31.920 ;
    END
  END periph_oe_14
  PIN periph_oe_15
    DIRECTION INPUT ;
    USE SIGNAL ;
    ANTENNAGATEAREA 0.647700 ;
    ANTENNADIFFAREA 0.434700 ;
    PORT
      LAYER met2 ;
        RECT 267.810 0.000 268.090 0.280 ;
    END
  END periph_oe_15
  PIN periph_oe_16
    DIRECTION INPUT ;
    USE SIGNAL ;
    ANTENNAGATEAREA 0.647700 ;
    ANTENNADIFFAREA 0.434700 ;
    PORT
      LAYER met2 ;
        RECT 315.650 0.000 315.930 0.280 ;
    END
  END periph_oe_16
  PIN periph_oe_17
    DIRECTION INPUT ;
    USE SIGNAL ;
    ANTENNAGATEAREA 0.647700 ;
    ANTENNADIFFAREA 0.434700 ;
    PORT
      LAYER met2 ;
        RECT 276.090 0.000 276.370 0.280 ;
    END
  END periph_oe_17
  PIN periph_oe_18
    DIRECTION INPUT ;
    USE SIGNAL ;
    ANTENNAGATEAREA 0.647700 ;
    ANTENNADIFFAREA 0.434700 ;
    PORT
      LAYER met2 ;
        RECT 307.370 0.000 307.650 0.280 ;
    END
  END periph_oe_18
  PIN periph_oe_19
    DIRECTION INPUT ;
    USE SIGNAL ;
    ANTENNAGATEAREA 0.647700 ;
    ANTENNADIFFAREA 0.434700 ;
    PORT
      LAYER met2 ;
        RECT 268.730 0.000 269.010 0.280 ;
    END
  END periph_oe_19
  PIN periph_oe_2
    DIRECTION INPUT ;
    USE SIGNAL ;
    ANTENNAGATEAREA 0.647700 ;
    ANTENNADIFFAREA 0.434700 ;
    PORT
      LAYER met2 ;
        RECT 272.410 0.000 272.690 0.280 ;
    END
  END periph_oe_2
  PIN periph_oe_20
    DIRECTION INPUT ;
    USE SIGNAL ;
    ANTENNAGATEAREA 0.647700 ;
    ANTENNADIFFAREA 0.434700 ;
    PORT
      LAYER met2 ;
        RECT 312.890 0.000 313.170 0.280 ;
    END
  END periph_oe_20
  PIN periph_oe_21
    DIRECTION INPUT ;
    USE SIGNAL ;
    ANTENNAGATEAREA 0.647700 ;
    ANTENNADIFFAREA 0.434700 ;
    PORT
      LAYER met2 ;
        RECT 269.650 0.000 269.930 0.280 ;
    END
  END periph_oe_21
  PIN periph_oe_22
    DIRECTION INPUT ;
    USE SIGNAL ;
    ANTENNAGATEAREA 0.647700 ;
    ANTENNADIFFAREA 0.434700 ;
    PORT
      LAYER met2 ;
        RECT 287.130 0.000 287.410 0.280 ;
    END
  END periph_oe_22
  PIN periph_oe_23
    DIRECTION INPUT ;
    USE SIGNAL ;
    ANTENNAGATEAREA 0.647700 ;
    ANTENNADIFFAREA 0.434700 ;
    PORT
      LAYER met2 ;
        RECT 305.530 0.000 305.810 0.280 ;
    END
  END periph_oe_23
  PIN periph_oe_24
    DIRECTION INPUT ;
    USE SIGNAL ;
    ANTENNAGATEAREA 0.647700 ;
    ANTENNADIFFAREA 0.434700 ;
    PORT
      LAYER met2 ;
        RECT 308.290 0.000 308.570 0.280 ;
    END
  END periph_oe_24
  PIN periph_oe_25
    DIRECTION INPUT ;
    USE SIGNAL ;
    ANTENNAGATEAREA 0.647700 ;
    ANTENNADIFFAREA 0.434700 ;
    PORT
      LAYER met2 ;
        RECT 273.330 0.000 273.610 0.280 ;
    END
  END periph_oe_25
  PIN periph_oe_26
    DIRECTION INPUT ;
    USE SIGNAL ;
    ANTENNAGATEAREA 0.647700 ;
    ANTENNADIFFAREA 0.434700 ;
    PORT
      LAYER met2 ;
        RECT 309.210 0.000 309.490 0.280 ;
    END
  END periph_oe_26
  PIN periph_oe_27
    DIRECTION INPUT ;
    USE SIGNAL ;
    ANTENNAGATEAREA 0.647700 ;
    ANTENNADIFFAREA 0.434700 ;
    PORT
      LAYER met2 ;
        RECT 290.810 0.000 291.090 0.280 ;
    END
  END periph_oe_27
  PIN periph_oe_28
    DIRECTION INPUT ;
    USE SIGNAL ;
    ANTENNAGATEAREA 0.647700 ;
    ANTENNADIFFAREA 0.434700 ;
    PORT
      LAYER met2 ;
        RECT 271.490 0.000 271.770 0.280 ;
    END
  END periph_oe_28
  PIN periph_oe_29
    DIRECTION INPUT ;
    USE SIGNAL ;
    ANTENNAGATEAREA 0.647700 ;
    ANTENNADIFFAREA 0.434700 ;
    PORT
      LAYER met2 ;
        RECT 302.770 0.000 303.050 0.280 ;
    END
  END periph_oe_29
  PIN periph_oe_3
    DIRECTION INPUT ;
    USE SIGNAL ;
    ANTENNAGATEAREA 0.647700 ;
    ANTENNADIFFAREA 0.434700 ;
    PORT
      LAYER met2 ;
        RECT 311.970 0.000 312.250 0.280 ;
    END
  END periph_oe_3
  PIN periph_oe_30
    DIRECTION INPUT ;
    USE SIGNAL ;
    ANTENNAGATEAREA 0.647700 ;
    ANTENNADIFFAREA 0.434700 ;
    PORT
      LAYER met2 ;
        RECT 298.170 0.000 298.450 0.280 ;
    END
  END periph_oe_30
  PIN periph_oe_31
    DIRECTION INPUT ;
    USE SIGNAL ;
    ANTENNAGATEAREA 0.647700 ;
    ANTENNADIFFAREA 0.434700 ;
    PORT
      LAYER met2 ;
        RECT 316.570 0.000 316.850 0.280 ;
    END
  END periph_oe_31
  PIN periph_oe_4
    DIRECTION INPUT ;
    USE SIGNAL ;
    ANTENNAGATEAREA 0.647700 ;
    ANTENNADIFFAREA 0.434700 ;
    PORT
      LAYER met2 ;
        RECT 310.130 0.000 310.410 0.280 ;
    END
  END periph_oe_4
  PIN periph_oe_5
    DIRECTION INPUT ;
    USE SIGNAL ;
    ANTENNAGATEAREA 0.647700 ;
    ANTENNADIFFAREA 0.434700 ;
    PORT
      LAYER met2 ;
        RECT 270.570 0.000 270.850 0.280 ;
    END
  END periph_oe_5
  PIN periph_oe_6
    DIRECTION INPUT ;
    USE SIGNAL ;
    ANTENNAGATEAREA 0.647700 ;
    ANTENNADIFFAREA 0.434700 ;
    PORT
      LAYER met2 ;
        RECT 318.410 0.000 318.690 0.280 ;
    END
  END periph_oe_6
  PIN periph_oe_7
    DIRECTION INPUT ;
    USE SIGNAL ;
    ANTENNAGATEAREA 0.647700 ;
    ANTENNADIFFAREA 0.434700 ;
    PORT
      LAYER met2 ;
        RECT 314.730 0.000 315.010 0.280 ;
    END
  END periph_oe_7
  PIN periph_oe_8
    DIRECTION INPUT ;
    USE SIGNAL ;
    ANTENNAGATEAREA 0.647700 ;
    ANTENNADIFFAREA 0.434700 ;
    PORT
      LAYER met2 ;
        RECT 281.610 0.000 281.890 0.280 ;
    END
  END periph_oe_8
  PIN periph_oe_9
    DIRECTION INPUT ;
    USE SIGNAL ;
    ANTENNAGATEAREA 0.647700 ;
    ANTENNADIFFAREA 0.434700 ;
    PORT
      LAYER met2 ;
        RECT 311.050 0.000 311.330 0.280 ;
    END
  END periph_oe_9
  PIN rst_n
    DIRECTION INPUT ;
    USE SIGNAL ;
    ANTENNAGATEAREA 0.647700 ;
    ANTENNADIFFAREA 0.434700 ;
    PORT
      LAYER met2 ;
        RECT 61.730 0.000 62.010 0.280 ;
    END
  END rst_n
  PIN s_axi_araddr_0
    DIRECTION INPUT ;
    USE SIGNAL ;
    ANTENNAGATEAREA 0.647700 ;
    ANTENNADIFFAREA 0.434700 ;
    PORT
      LAYER met2 ;
        RECT 254.010 378.705 254.290 378.985 ;
    END
  END s_axi_araddr_0
  PIN s_axi_araddr_1
    DIRECTION INPUT ;
    USE SIGNAL ;
    ANTENNAGATEAREA 0.647700 ;
    ANTENNADIFFAREA 0.434700 ;
    PORT
      LAYER met2 ;
        RECT 237.450 378.705 237.730 378.985 ;
    END
  END s_axi_araddr_1
  PIN s_axi_araddr_10
    DIRECTION INPUT ;
    USE SIGNAL ;
    ANTENNAGATEAREA 0.647700 ;
    ANTENNADIFFAREA 0.434700 ;
    PORT
      LAYER met2 ;
        RECT 243.890 378.705 244.170 378.985 ;
    END
  END s_axi_araddr_10
  PIN s_axi_araddr_11
    DIRECTION INPUT ;
    USE SIGNAL ;
    ANTENNAGATEAREA 0.647700 ;
    ANTENNADIFFAREA 0.434700 ;
    PORT
      LAYER met2 ;
        RECT 220.890 378.705 221.170 378.985 ;
    END
  END s_axi_araddr_11
  PIN s_axi_araddr_2
    DIRECTION INPUT ;
    USE SIGNAL ;
    ANTENNAGATEAREA 0.647700 ;
    ANTENNADIFFAREA 0.434700 ;
    PORT
      LAYER met2 ;
        RECT 219.050 378.705 219.330 378.985 ;
    END
  END s_axi_araddr_2
  PIN s_axi_araddr_3
    DIRECTION INPUT ;
    USE SIGNAL ;
    ANTENNAGATEAREA 0.647700 ;
    ANTENNADIFFAREA 0.434700 ;
    PORT
      LAYER met2 ;
        RECT 270.570 378.705 270.850 378.985 ;
    END
  END s_axi_araddr_3
  PIN s_axi_araddr_4
    DIRECTION INPUT ;
    USE SIGNAL ;
    ANTENNAGATEAREA 0.647700 ;
    ANTENNADIFFAREA 0.434700 ;
    PORT
      LAYER met2 ;
        RECT 277.930 378.705 278.210 378.985 ;
    END
  END s_axi_araddr_4
  PIN s_axi_araddr_5
    DIRECTION INPUT ;
    USE SIGNAL ;
    ANTENNAGATEAREA 0.647700 ;
    ANTENNADIFFAREA 0.434700 ;
    PORT
      LAYER met2 ;
        RECT 278.850 378.705 279.130 378.985 ;
    END
  END s_axi_araddr_5
  PIN s_axi_araddr_6
    DIRECTION INPUT ;
    USE SIGNAL ;
    ANTENNAGATEAREA 0.647700 ;
    ANTENNADIFFAREA 0.434700 ;
    PORT
      LAYER met2 ;
        RECT 262.290 378.705 262.570 378.985 ;
    END
  END s_axi_araddr_6
  PIN s_axi_araddr_7
    DIRECTION INPUT ;
    USE SIGNAL ;
    ANTENNAGATEAREA 0.647700 ;
    ANTENNADIFFAREA 0.434700 ;
    PORT
      LAYER met2 ;
        RECT 247.570 378.705 247.850 378.985 ;
    END
  END s_axi_araddr_7
  PIN s_axi_araddr_8
    DIRECTION INPUT ;
    USE SIGNAL ;
    ANTENNAGATEAREA 0.647700 ;
    ANTENNADIFFAREA 0.434700 ;
    PORT
      LAYER met2 ;
        RECT 229.170 378.705 229.450 378.985 ;
    END
  END s_axi_araddr_8
  PIN s_axi_araddr_9
    DIRECTION INPUT ;
    USE SIGNAL ;
    ANTENNAGATEAREA 0.647700 ;
    ANTENNADIFFAREA 0.434700 ;
    PORT
      LAYER met2 ;
        RECT 213.530 378.705 213.810 378.985 ;
    END
  END s_axi_araddr_9
  PIN s_axi_arready
    DIRECTION OUTPUT ;
    USE SIGNAL ;
    ANTENNAGATEAREA 0.434700 ;
    ANTENNADIFFAREA 1.137600 ;
    PORT
      LAYER met2 ;
        RECT 288.050 378.705 288.330 378.985 ;
    END
  END s_axi_arready
  PIN s_axi_arvalid
    DIRECTION INPUT ;
    USE SIGNAL ;
    ANTENNAGATEAREA 0.647700 ;
    ANTENNADIFFAREA 0.434700 ;
    PORT
      LAYER met2 ;
        RECT 279.770 378.705 280.050 378.985 ;
    END
  END s_axi_arvalid
  PIN s_axi_awaddr_0
    DIRECTION INPUT ;
    USE SIGNAL ;
    ANTENNAGATEAREA 0.647700 ;
    ANTENNADIFFAREA 0.434700 ;
    PORT
      LAYER met3 ;
        RECT 0.000 205.400 0.600 206.000 ;
    END
  END s_axi_awaddr_0
  PIN s_axi_awaddr_1
    DIRECTION INPUT ;
    USE SIGNAL ;
    ANTENNAGATEAREA 0.647700 ;
    ANTENNADIFFAREA 0.434700 ;
    PORT
      LAYER met3 ;
        RECT 0.000 206.760 0.600 207.360 ;
    END
  END s_axi_awaddr_1
  PIN s_axi_awaddr_10
    DIRECTION INPUT ;
    USE SIGNAL ;
    ANTENNAGATEAREA 0.647700 ;
    ANTENNADIFFAREA 0.434700 ;
    PORT
      LAYER met3 ;
        RECT 0.000 244.840 0.600 245.440 ;
    END
  END s_axi_awaddr_10
  PIN s_axi_awaddr_11
    DIRECTION INPUT ;
    USE SIGNAL ;
    ANTENNAGATEAREA 0.647700 ;
    ANTENNADIFFAREA 0.434700 ;
    PORT
      LAYER met3 ;
        RECT 0.000 246.200 0.600 246.800 ;
    END
  END s_axi_awaddr_11
  PIN s_axi_awaddr_2
    DIRECTION INPUT ;
    USE SIGNAL ;
    ANTENNAGATEAREA 0.647700 ;
    ANTENNADIFFAREA 0.434700 ;
    PORT
      LAYER met3 ;
        RECT 0.000 221.720 0.600 222.320 ;
    END
  END s_axi_awaddr_2
  PIN s_axi_awaddr_3
    DIRECTION INPUT ;
    USE SIGNAL ;
    ANTENNAGATEAREA 0.647700 ;
    ANTENNADIFFAREA 0.434700 ;
    PORT
      LAYER met3 ;
        RECT 0.000 242.120 0.600 242.720 ;
    END
  END s_axi_awaddr_3
  PIN s_axi_awaddr_4
    DIRECTION INPUT ;
    USE SIGNAL ;
    ANTENNAGATEAREA 0.647700 ;
    ANTENNADIFFAREA 0.434700 ;
    PORT
      LAYER met3 ;
        RECT 0.000 232.600 0.600 233.200 ;
    END
  END s_axi_awaddr_4
  PIN s_axi_awaddr_5
    DIRECTION INPUT ;
    USE SIGNAL ;
    ANTENNAGATEAREA 0.647700 ;
    ANTENNADIFFAREA 0.434700 ;
    PORT
      LAYER met3 ;
        RECT 0.000 216.280 0.600 216.880 ;
    END
  END s_axi_awaddr_5
  PIN s_axi_awaddr_6
    DIRECTION INPUT ;
    USE SIGNAL ;
    ANTENNAGATEAREA 0.647700 ;
    ANTENNADIFFAREA 0.434700 ;
    PORT
      LAYER met3 ;
        RECT 0.000 223.080 0.600 223.680 ;
    END
  END s_axi_awaddr_6
  PIN s_axi_awaddr_7
    DIRECTION INPUT ;
    USE SIGNAL ;
    ANTENNAGATEAREA 0.647700 ;
    ANTENNADIFFAREA 0.434700 ;
    PORT
      LAYER met3 ;
        RECT 0.000 214.920 0.600 215.520 ;
    END
  END s_axi_awaddr_7
  PIN s_axi_awaddr_8
    DIRECTION INPUT ;
    USE SIGNAL ;
    ANTENNAGATEAREA 0.647700 ;
    ANTENNADIFFAREA 0.434700 ;
    PORT
      LAYER met3 ;
        RECT 0.000 225.800 0.600 226.400 ;
    END
  END s_axi_awaddr_8
  PIN s_axi_awaddr_9
    DIRECTION INPUT ;
    USE SIGNAL ;
    ANTENNAGATEAREA 0.647700 ;
    ANTENNADIFFAREA 0.434700 ;
    PORT
      LAYER met3 ;
        RECT 0.000 243.480 0.600 244.080 ;
    END
  END s_axi_awaddr_9
  PIN s_axi_awready
    DIRECTION OUTPUT ;
    USE SIGNAL ;
    ANTENNAGATEAREA 0.434700 ;
    ANTENNADIFFAREA 1.137600 ;
    PORT
      LAYER met3 ;
        RECT 0.000 194.520 0.600 195.120 ;
    END
  END s_axi_awready
  PIN s_axi_awvalid
    DIRECTION INPUT ;
    USE SIGNAL ;
    ANTENNAGATEAREA 0.647700 ;
    ANTENNADIFFAREA 0.434700 ;
    PORT
      LAYER met3 ;
        RECT 0.000 202.680 0.600 203.280 ;
    END
  END s_axi_awvalid
  PIN s_axi_bready
    DIRECTION INPUT ;
    USE SIGNAL ;
    PORT
      LAYER met2 ;
        RECT 62.650 0.000 62.930 0.280 ;
    END
  END s_axi_bready
  PIN s_axi_bresp_0
    DIRECTION OUTPUT ;
    USE SIGNAL ;
    PORT
      LAYER met2 ;
        RECT 63.570 0.000 63.850 0.280 ;
    END
  END s_axi_bresp_0
  PIN s_axi_bresp_1
    DIRECTION OUTPUT ;
    USE SIGNAL ;
    PORT
      LAYER met2 ;
        RECT 64.490 0.000 64.770 0.280 ;
    END
  END s_axi_bresp_1
  PIN s_axi_bvalid
    DIRECTION OUTPUT ;
    USE SIGNAL ;
    PORT
      LAYER met2 ;
        RECT 65.410 0.000 65.690 0.280 ;
    END
  END s_axi_bvalid
  PIN s_axi_rdata_0
    DIRECTION OUTPUT ;
    USE SIGNAL ;
    ANTENNAGATEAREA 0.434700 ;
    ANTENNADIFFAREA 1.137600 ;
    PORT
      LAYER met2 ;
        RECT 219.970 378.705 220.250 378.985 ;
    END
  END s_axi_rdata_0
  PIN s_axi_rdata_1
    DIRECTION OUTPUT ;
    USE SIGNAL ;
    ANTENNAGATEAREA 0.434700 ;
    ANTENNADIFFAREA 1.137600 ;
    PORT
      LAYER met2 ;
        RECT 181.330 378.705 181.610 378.985 ;
    END
  END s_axi_rdata_1
  PIN s_axi_rdata_10
    DIRECTION OUTPUT ;
    USE SIGNAL ;
    ANTENNAGATEAREA 0.434700 ;
    ANTENNADIFFAREA 1.137600 ;
    PORT
      LAYER met2 ;
        RECT 246.650 378.705 246.930 378.985 ;
    END
  END s_axi_rdata_10
  PIN s_axi_rdata_11
    DIRECTION OUTPUT ;
    USE SIGNAL ;
    ANTENNAGATEAREA 0.434700 ;
    ANTENNADIFFAREA 1.137600 ;
    PORT
      LAYER met2 ;
        RECT 267.810 378.705 268.090 378.985 ;
    END
  END s_axi_rdata_11
  PIN s_axi_rdata_12
    DIRECTION OUTPUT ;
    USE SIGNAL ;
    ANTENNAGATEAREA 0.434700 ;
    ANTENNADIFFAREA 1.137600 ;
    PORT
      LAYER met2 ;
        RECT 179.490 378.705 179.770 378.985 ;
    END
  END s_axi_rdata_12
  PIN s_axi_rdata_13
    DIRECTION OUTPUT ;
    USE SIGNAL ;
    ANTENNAGATEAREA 0.434700 ;
    ANTENNADIFFAREA 1.137600 ;
    PORT
      LAYER met2 ;
        RECT 223.650 378.705 223.930 378.985 ;
    END
  END s_axi_rdata_13
  PIN s_axi_rdata_14
    DIRECTION OUTPUT ;
    USE SIGNAL ;
    ANTENNAGATEAREA 0.434700 ;
    ANTENNADIFFAREA 1.137600 ;
    PORT
      LAYER met2 ;
        RECT 245.730 378.705 246.010 378.985 ;
    END
  END s_axi_rdata_14
  PIN s_axi_rdata_15
    DIRECTION OUTPUT ;
    USE SIGNAL ;
    ANTENNAGATEAREA 0.434700 ;
    ANTENNADIFFAREA 1.137600 ;
    PORT
      LAYER met2 ;
        RECT 265.970 378.705 266.250 378.985 ;
    END
  END s_axi_rdata_15
  PIN s_axi_rdata_16
    DIRECTION OUTPUT ;
    USE SIGNAL ;
    ANTENNAGATEAREA 0.434700 ;
    ANTENNADIFFAREA 1.137600 ;
    PORT
      LAYER met2 ;
        RECT 201.570 378.705 201.850 378.985 ;
    END
  END s_axi_rdata_16
  PIN s_axi_rdata_17
    DIRECTION OUTPUT ;
    USE SIGNAL ;
    ANTENNAGATEAREA 0.434700 ;
    ANTENNADIFFAREA 1.137600 ;
    PORT
      LAYER met2 ;
        RECT 287.130 378.705 287.410 378.985 ;
    END
  END s_axi_rdata_17
  PIN s_axi_rdata_18
    DIRECTION OUTPUT ;
    USE SIGNAL ;
    ANTENNAGATEAREA 0.434700 ;
    ANTENNADIFFAREA 1.137600 ;
    PORT
      LAYER met2 ;
        RECT 178.570 378.705 178.850 378.985 ;
    END
  END s_axi_rdata_18
  PIN s_axi_rdata_19
    DIRECTION OUTPUT ;
    USE SIGNAL ;
    ANTENNAGATEAREA 0.434700 ;
    ANTENNADIFFAREA 1.137600 ;
    PORT
      LAYER met2 ;
        RECT 258.610 378.705 258.890 378.985 ;
    END
  END s_axi_rdata_19
  PIN s_axi_rdata_2
    DIRECTION OUTPUT ;
    USE SIGNAL ;
    ANTENNAGATEAREA 0.434700 ;
    ANTENNADIFFAREA 1.137600 ;
    PORT
      LAYER met2 ;
        RECT 176.730 378.705 177.010 378.985 ;
    END
  END s_axi_rdata_2
  PIN s_axi_rdata_20
    DIRECTION OUTPUT ;
    USE SIGNAL ;
    ANTENNAGATEAREA 0.434700 ;
    ANTENNADIFFAREA 1.137600 ;
    PORT
      LAYER met2 ;
        RECT 252.170 378.705 252.450 378.985 ;
    END
  END s_axi_rdata_20
  PIN s_axi_rdata_21
    DIRECTION OUTPUT ;
    USE SIGNAL ;
    ANTENNAGATEAREA 0.434700 ;
    ANTENNADIFFAREA 1.137600 ;
    PORT
      LAYER met2 ;
        RECT 286.210 378.705 286.490 378.985 ;
    END
  END s_axi_rdata_21
  PIN s_axi_rdata_22
    DIRECTION OUTPUT ;
    USE SIGNAL ;
    ANTENNAGATEAREA 0.434700 ;
    ANTENNADIFFAREA 1.137600 ;
    PORT
      LAYER met2 ;
        RECT 285.290 378.705 285.570 378.985 ;
    END
  END s_axi_rdata_22
  PIN s_axi_rdata_23
    DIRECTION OUTPUT ;
    USE SIGNAL ;
    ANTENNAGATEAREA 0.434700 ;
    ANTENNADIFFAREA 1.137600 ;
    PORT
      LAYER met2 ;
        RECT 284.370 378.705 284.650 378.985 ;
    END
  END s_axi_rdata_23
  PIN s_axi_rdata_24
    DIRECTION OUTPUT ;
    USE SIGNAL ;
    ANTENNAGATEAREA 0.434700 ;
    ANTENNADIFFAREA 1.137600 ;
    PORT
      LAYER met2 ;
        RECT 242.050 378.705 242.330 378.985 ;
    END
  END s_axi_rdata_24
  PIN s_axi_rdata_25
    DIRECTION OUTPUT ;
    USE SIGNAL ;
    ANTENNAGATEAREA 0.434700 ;
    ANTENNADIFFAREA 1.137600 ;
    PORT
      LAYER met2 ;
        RECT 283.450 378.705 283.730 378.985 ;
    END
  END s_axi_rdata_25
  PIN s_axi_rdata_26
    DIRECTION OUTPUT ;
    USE SIGNAL ;
    ANTENNAGATEAREA 0.434700 ;
    ANTENNADIFFAREA 1.137600 ;
    PORT
      LAYER met2 ;
        RECT 199.730 378.705 200.010 378.985 ;
    END
  END s_axi_rdata_26
  PIN s_axi_rdata_27
    DIRECTION OUTPUT ;
    USE SIGNAL ;
    ANTENNAGATEAREA 0.434700 ;
    ANTENNADIFFAREA 1.137600 ;
    PORT
      LAYER met2 ;
        RECT 271.490 378.705 271.770 378.985 ;
    END
  END s_axi_rdata_27
  PIN s_axi_rdata_28
    DIRECTION OUTPUT ;
    USE SIGNAL ;
    ANTENNAGATEAREA 0.434700 ;
    ANTENNADIFFAREA 1.137600 ;
    PORT
      LAYER met2 ;
        RECT 202.490 378.705 202.770 378.985 ;
    END
  END s_axi_rdata_28
  PIN s_axi_rdata_29
    DIRECTION OUTPUT ;
    USE SIGNAL ;
    ANTENNAGATEAREA 0.434700 ;
    ANTENNADIFFAREA 1.137600 ;
    PORT
      LAYER met2 ;
        RECT 200.650 378.705 200.930 378.985 ;
    END
  END s_axi_rdata_29
  PIN s_axi_rdata_3
    DIRECTION OUTPUT ;
    USE SIGNAL ;
    ANTENNAGATEAREA 0.434700 ;
    ANTENNADIFFAREA 1.137600 ;
    PORT
      LAYER met2 ;
        RECT 266.890 378.705 267.170 378.985 ;
    END
  END s_axi_rdata_3
  PIN s_axi_rdata_30
    DIRECTION OUTPUT ;
    USE SIGNAL ;
    ANTENNAGATEAREA 0.434700 ;
    ANTENNADIFFAREA 1.137600 ;
    PORT
      LAYER met2 ;
        RECT 218.130 378.705 218.410 378.985 ;
    END
  END s_axi_rdata_30
  PIN s_axi_rdata_31
    DIRECTION OUTPUT ;
    USE SIGNAL ;
    ANTENNAGATEAREA 0.434700 ;
    ANTENNADIFFAREA 1.137600 ;
    PORT
      LAYER met2 ;
        RECT 225.490 378.705 225.770 378.985 ;
    END
  END s_axi_rdata_31
  PIN s_axi_rdata_4
    DIRECTION OUTPUT ;
    USE SIGNAL ;
    ANTENNAGATEAREA 0.434700 ;
    ANTENNADIFFAREA 1.137600 ;
    PORT
      LAYER met2 ;
        RECT 224.570 378.705 224.850 378.985 ;
    END
  END s_axi_rdata_4
  PIN s_axi_rdata_5
    DIRECTION OUTPUT ;
    USE SIGNAL ;
    ANTENNAGATEAREA 0.434700 ;
    ANTENNADIFFAREA 1.137600 ;
    PORT
      LAYER met2 ;
        RECT 206.170 378.705 206.450 378.985 ;
    END
  END s_axi_rdata_5
  PIN s_axi_rdata_6
    DIRECTION OUTPUT ;
    USE SIGNAL ;
    ANTENNAGATEAREA 0.434700 ;
    ANTENNADIFFAREA 1.137600 ;
    PORT
      LAYER met2 ;
        RECT 265.050 378.705 265.330 378.985 ;
    END
  END s_axi_rdata_6
  PIN s_axi_rdata_7
    DIRECTION OUTPUT ;
    USE SIGNAL ;
    ANTENNAGATEAREA 0.434700 ;
    ANTENNADIFFAREA 1.137600 ;
    PORT
      LAYER met2 ;
        RECT 185.930 378.705 186.210 378.985 ;
    END
  END s_axi_rdata_7
  PIN s_axi_rdata_8
    DIRECTION OUTPUT ;
    USE SIGNAL ;
    ANTENNAGATEAREA 0.434700 ;
    ANTENNADIFFAREA 1.137600 ;
    PORT
      LAYER met2 ;
        RECT 177.650 378.705 177.930 378.985 ;
    END
  END s_axi_rdata_8
  PIN s_axi_rdata_9
    DIRECTION OUTPUT ;
    USE SIGNAL ;
    ANTENNAGATEAREA 0.434700 ;
    ANTENNADIFFAREA 1.137600 ;
    PORT
      LAYER met2 ;
        RECT 238.370 378.705 238.650 378.985 ;
    END
  END s_axi_rdata_9
  PIN s_axi_rready
    DIRECTION INPUT ;
    USE SIGNAL ;
    ANTENNAGATEAREA 0.647700 ;
    ANTENNADIFFAREA 0.434700 ;
    PORT
      LAYER met2 ;
        RECT 207.090 378.705 207.370 378.985 ;
    END
  END s_axi_rready
  PIN s_axi_rresp_0
    DIRECTION OUTPUT ;
    USE SIGNAL ;
    ANTENNAGATEAREA 0.434700 ;
    ANTENNADIFFAREA 1.137600 ;
    PORT
      LAYER met2 ;
        RECT 264.130 378.705 264.410 378.985 ;
    END
  END s_axi_rresp_0
  PIN s_axi_rresp_1
    DIRECTION OUTPUT ;
    USE SIGNAL ;
    ANTENNAGATEAREA 0.434700 ;
    ANTENNADIFFAREA 1.137600 ;
    PORT
      LAYER met2 ;
        RECT 244.810 378.705 245.090 378.985 ;
    END
  END s_axi_rresp_1
  PIN s_axi_rvalid
    DIRECTION OUTPUT ;
    USE SIGNAL ;
    ANTENNAGATEAREA 0.434700 ;
    ANTENNADIFFAREA 1.137600 ;
    PORT
      LAYER met2 ;
        RECT 205.250 378.705 205.530 378.985 ;
    END
  END s_axi_rvalid
  PIN s_axi_wdata_0
    DIRECTION INPUT ;
    USE SIGNAL ;
    PORT
      LAYER met2 ;
        RECT 66.330 0.000 66.610 0.280 ;
    END
  END s_axi_wdata_0
  PIN s_axi_wdata_1
    DIRECTION INPUT ;
    USE SIGNAL ;
    PORT
      LAYER met2 ;
        RECT 67.250 0.000 67.530 0.280 ;
    END
  END s_axi_wdata_1
  PIN s_axi_wdata_10
    DIRECTION INPUT ;
    USE SIGNAL ;
    PORT
      LAYER met2 ;
        RECT 68.170 0.000 68.450 0.280 ;
    END
  END s_axi_wdata_10
  PIN s_axi_wdata_11
    DIRECTION INPUT ;
    USE SIGNAL ;
    PORT
      LAYER met2 ;
        RECT 69.090 0.000 69.370 0.280 ;
    END
  END s_axi_wdata_11
  PIN s_axi_wdata_12
    DIRECTION INPUT ;
    USE SIGNAL ;
    PORT
      LAYER met2 ;
        RECT 70.010 0.000 70.290 0.280 ;
    END
  END s_axi_wdata_12
  PIN s_axi_wdata_13
    DIRECTION INPUT ;
    USE SIGNAL ;
    PORT
      LAYER met2 ;
        RECT 70.930 0.000 71.210 0.280 ;
    END
  END s_axi_wdata_13
  PIN s_axi_wdata_14
    DIRECTION INPUT ;
    USE SIGNAL ;
    PORT
      LAYER met2 ;
        RECT 71.850 0.000 72.130 0.280 ;
    END
  END s_axi_wdata_14
  PIN s_axi_wdata_15
    DIRECTION INPUT ;
    USE SIGNAL ;
    PORT
      LAYER met2 ;
        RECT 72.770 0.000 73.050 0.280 ;
    END
  END s_axi_wdata_15
  PIN s_axi_wdata_16
    DIRECTION INPUT ;
    USE SIGNAL ;
    PORT
      LAYER met2 ;
        RECT 73.690 0.000 73.970 0.280 ;
    END
  END s_axi_wdata_16
  PIN s_axi_wdata_17
    DIRECTION INPUT ;
    USE SIGNAL ;
    PORT
      LAYER met2 ;
        RECT 74.610 0.000 74.890 0.280 ;
    END
  END s_axi_wdata_17
  PIN s_axi_wdata_18
    DIRECTION INPUT ;
    USE SIGNAL ;
    PORT
      LAYER met2 ;
        RECT 75.530 0.000 75.810 0.280 ;
    END
  END s_axi_wdata_18
  PIN s_axi_wdata_19
    DIRECTION INPUT ;
    USE SIGNAL ;
    PORT
      LAYER met2 ;
        RECT 76.450 0.000 76.730 0.280 ;
    END
  END s_axi_wdata_19
  PIN s_axi_wdata_2
    DIRECTION INPUT ;
    USE SIGNAL ;
    PORT
      LAYER met2 ;
        RECT 77.370 0.000 77.650 0.280 ;
    END
  END s_axi_wdata_2
  PIN s_axi_wdata_20
    DIRECTION INPUT ;
    USE SIGNAL ;
    PORT
      LAYER met2 ;
        RECT 78.290 0.000 78.570 0.280 ;
    END
  END s_axi_wdata_20
  PIN s_axi_wdata_21
    DIRECTION INPUT ;
    USE SIGNAL ;
    PORT
      LAYER met2 ;
        RECT 79.210 0.000 79.490 0.280 ;
    END
  END s_axi_wdata_21
  PIN s_axi_wdata_22
    DIRECTION INPUT ;
    USE SIGNAL ;
    PORT
      LAYER met2 ;
        RECT 80.130 0.000 80.410 0.280 ;
    END
  END s_axi_wdata_22
  PIN s_axi_wdata_23
    DIRECTION INPUT ;
    USE SIGNAL ;
    PORT
      LAYER met2 ;
        RECT 81.050 0.000 81.330 0.280 ;
    END
  END s_axi_wdata_23
  PIN s_axi_wdata_24
    DIRECTION INPUT ;
    USE SIGNAL ;
    PORT
      LAYER met2 ;
        RECT 81.970 0.000 82.250 0.280 ;
    END
  END s_axi_wdata_24
  PIN s_axi_wdata_25
    DIRECTION INPUT ;
    USE SIGNAL ;
    PORT
      LAYER met2 ;
        RECT 82.890 0.000 83.170 0.280 ;
    END
  END s_axi_wdata_25
  PIN s_axi_wdata_26
    DIRECTION INPUT ;
    USE SIGNAL ;
    PORT
      LAYER met2 ;
        RECT 83.810 0.000 84.090 0.280 ;
    END
  END s_axi_wdata_26
  PIN s_axi_wdata_27
    DIRECTION INPUT ;
    USE SIGNAL ;
    PORT
      LAYER met2 ;
        RECT 84.730 0.000 85.010 0.280 ;
    END
  END s_axi_wdata_27
  PIN s_axi_wdata_28
    DIRECTION INPUT ;
    USE SIGNAL ;
    PORT
      LAYER met2 ;
        RECT 85.650 0.000 85.930 0.280 ;
    END
  END s_axi_wdata_28
  PIN s_axi_wdata_29
    DIRECTION INPUT ;
    USE SIGNAL ;
    PORT
      LAYER met2 ;
        RECT 86.570 0.000 86.850 0.280 ;
    END
  END s_axi_wdata_29
  PIN s_axi_wdata_3
    DIRECTION INPUT ;
    USE SIGNAL ;
    PORT
      LAYER met2 ;
        RECT 87.490 0.000 87.770 0.280 ;
    END
  END s_axi_wdata_3
  PIN s_axi_wdata_30
    DIRECTION INPUT ;
    USE SIGNAL ;
    PORT
      LAYER met2 ;
        RECT 88.410 0.000 88.690 0.280 ;
    END
  END s_axi_wdata_30
  PIN s_axi_wdata_31
    DIRECTION INPUT ;
    USE SIGNAL ;
    PORT
      LAYER met2 ;
        RECT 89.330 0.000 89.610 0.280 ;
    END
  END s_axi_wdata_31
  PIN s_axi_wdata_4
    DIRECTION INPUT ;
    USE SIGNAL ;
    PORT
      LAYER met2 ;
        RECT 90.250 0.000 90.530 0.280 ;
    END
  END s_axi_wdata_4
  PIN s_axi_wdata_5
    DIRECTION INPUT ;
    USE SIGNAL ;
    PORT
      LAYER met2 ;
        RECT 91.170 0.000 91.450 0.280 ;
    END
  END s_axi_wdata_5
  PIN s_axi_wdata_6
    DIRECTION INPUT ;
    USE SIGNAL ;
    PORT
      LAYER met2 ;
        RECT 92.090 0.000 92.370 0.280 ;
    END
  END s_axi_wdata_6
  PIN s_axi_wdata_7
    DIRECTION INPUT ;
    USE SIGNAL ;
    PORT
      LAYER met2 ;
        RECT 93.010 0.000 93.290 0.280 ;
    END
  END s_axi_wdata_7
  PIN s_axi_wdata_8
    DIRECTION INPUT ;
    USE SIGNAL ;
    PORT
      LAYER met2 ;
        RECT 93.930 0.000 94.210 0.280 ;
    END
  END s_axi_wdata_8
  PIN s_axi_wdata_9
    DIRECTION INPUT ;
    USE SIGNAL ;
    PORT
      LAYER met2 ;
        RECT 94.850 0.000 95.130 0.280 ;
    END
  END s_axi_wdata_9
  PIN s_axi_wready
    DIRECTION OUTPUT ;
    USE SIGNAL ;
    ANTENNAGATEAREA 0.434700 ;
    ANTENNADIFFAREA 1.137600 ;
    PORT
      LAYER met3 ;
        RECT 0.000 190.440 0.600 191.040 ;
    END
  END s_axi_wready
  PIN s_axi_wstrb_0
    DIRECTION INPUT ;
    USE SIGNAL ;
    PORT
      LAYER met2 ;
        RECT 95.770 0.000 96.050 0.280 ;
    END
  END s_axi_wstrb_0
  PIN s_axi_wstrb_1
    DIRECTION INPUT ;
    USE SIGNAL ;
    PORT
      LAYER met2 ;
        RECT 96.690 0.000 96.970 0.280 ;
    END
  END s_axi_wstrb_1
  PIN s_axi_wstrb_2
    DIRECTION INPUT ;
    USE SIGNAL ;
    PORT
      LAYER met2 ;
        RECT 97.610 0.000 97.890 0.280 ;
    END
  END s_axi_wstrb_2
  PIN s_axi_wstrb_3
    DIRECTION INPUT ;
    USE SIGNAL ;
    PORT
      LAYER met2 ;
        RECT 98.530 0.000 98.810 0.280 ;
    END
  END s_axi_wstrb_3
  PIN s_axi_wvalid
    DIRECTION INPUT ;
    USE SIGNAL ;
    ANTENNAGATEAREA 0.647700 ;
    ANTENNADIFFAREA 0.434700 ;
    PORT
      LAYER met3 ;
        RECT 0.000 199.960 0.600 200.560 ;
    END
  END s_axi_wvalid
  OBS
      LAYER nwell ;
        RECT 5.330 10.795 362.670 367.390 ;
      LAYER li1 ;
        RECT 5.520 10.795 362.480 367.285 ;
      LAYER met1 ;
        RECT 5.520 0.040 362.480 367.440 ;
      LAYER met2 ;
        RECT 5.610 378.425 176.450 378.915 ;
        RECT 177.290 378.425 177.370 378.915 ;
        RECT 178.210 378.425 178.290 378.915 ;
        RECT 179.130 378.425 179.210 378.915 ;
        RECT 180.050 378.425 181.050 378.915 ;
        RECT 181.890 378.425 185.650 378.915 ;
        RECT 186.490 378.425 199.450 378.915 ;
        RECT 200.290 378.425 200.370 378.915 ;
        RECT 201.210 378.425 201.290 378.915 ;
        RECT 202.130 378.425 202.210 378.915 ;
        RECT 203.050 378.425 204.970 378.915 ;
        RECT 205.810 378.425 205.890 378.915 ;
        RECT 206.730 378.425 206.810 378.915 ;
        RECT 207.650 378.425 213.250 378.915 ;
        RECT 214.090 378.425 217.850 378.915 ;
        RECT 218.690 378.425 218.770 378.915 ;
        RECT 219.610 378.425 219.690 378.915 ;
        RECT 220.530 378.425 220.610 378.915 ;
        RECT 221.450 378.425 223.370 378.915 ;
        RECT 224.210 378.425 224.290 378.915 ;
        RECT 225.130 378.425 225.210 378.915 ;
        RECT 226.050 378.425 228.890 378.915 ;
        RECT 229.730 378.425 237.170 378.915 ;
        RECT 238.010 378.425 238.090 378.915 ;
        RECT 238.930 378.425 241.770 378.915 ;
        RECT 242.610 378.425 243.610 378.915 ;
        RECT 244.450 378.425 244.530 378.915 ;
        RECT 245.370 378.425 245.450 378.915 ;
        RECT 246.290 378.425 246.370 378.915 ;
        RECT 247.210 378.425 247.290 378.915 ;
        RECT 248.130 378.425 251.890 378.915 ;
        RECT 252.730 378.425 253.730 378.915 ;
        RECT 254.570 378.425 258.330 378.915 ;
        RECT 259.170 378.425 262.010 378.915 ;
        RECT 262.850 378.425 263.850 378.915 ;
        RECT 264.690 378.425 264.770 378.915 ;
        RECT 265.610 378.425 265.690 378.915 ;
        RECT 266.530 378.425 266.610 378.915 ;
        RECT 267.450 378.425 267.530 378.915 ;
        RECT 268.370 378.425 270.290 378.915 ;
        RECT 271.130 378.425 271.210 378.915 ;
        RECT 272.050 378.425 277.650 378.915 ;
        RECT 278.490 378.425 278.570 378.915 ;
        RECT 279.410 378.425 279.490 378.915 ;
        RECT 280.330 378.425 283.170 378.915 ;
        RECT 284.010 378.425 284.090 378.915 ;
        RECT 284.930 378.425 285.010 378.915 ;
        RECT 285.850 378.425 285.930 378.915 ;
        RECT 286.770 378.425 286.850 378.915 ;
        RECT 287.690 378.425 287.770 378.915 ;
        RECT 288.610 378.425 362.390 378.915 ;
        RECT 5.610 0.560 362.390 378.425 ;
        RECT 6.170 0.010 6.250 0.560 ;
        RECT 7.090 0.010 7.170 0.560 ;
        RECT 8.010 0.010 8.090 0.560 ;
        RECT 8.930 0.010 9.010 0.560 ;
        RECT 9.850 0.010 9.930 0.560 ;
        RECT 10.770 0.010 10.850 0.560 ;
        RECT 11.690 0.010 11.770 0.560 ;
        RECT 12.610 0.010 12.690 0.560 ;
        RECT 13.530 0.010 13.610 0.560 ;
        RECT 14.450 0.010 14.530 0.560 ;
        RECT 15.370 0.010 15.450 0.560 ;
        RECT 16.290 0.010 16.370 0.560 ;
        RECT 17.210 0.010 17.290 0.560 ;
        RECT 18.130 0.010 18.210 0.560 ;
        RECT 19.050 0.010 19.130 0.560 ;
        RECT 19.970 0.010 20.050 0.560 ;
        RECT 20.890 0.010 20.970 0.560 ;
        RECT 21.810 0.010 21.890 0.560 ;
        RECT 22.730 0.010 22.810 0.560 ;
        RECT 23.650 0.010 23.730 0.560 ;
        RECT 24.570 0.010 24.650 0.560 ;
        RECT 25.490 0.010 25.570 0.560 ;
        RECT 26.410 0.010 26.490 0.560 ;
        RECT 27.330 0.010 27.410 0.560 ;
        RECT 28.250 0.010 28.330 0.560 ;
        RECT 29.170 0.010 29.250 0.560 ;
        RECT 30.090 0.010 30.170 0.560 ;
        RECT 31.010 0.010 31.090 0.560 ;
        RECT 31.930 0.010 32.010 0.560 ;
        RECT 32.850 0.010 32.930 0.560 ;
        RECT 33.770 0.010 33.850 0.560 ;
        RECT 34.690 0.010 34.770 0.560 ;
        RECT 35.610 0.010 35.690 0.560 ;
        RECT 36.530 0.010 36.610 0.560 ;
        RECT 37.450 0.010 37.530 0.560 ;
        RECT 38.370 0.010 38.450 0.560 ;
        RECT 39.290 0.010 39.370 0.560 ;
        RECT 40.210 0.010 40.290 0.560 ;
        RECT 41.130 0.010 41.210 0.560 ;
        RECT 42.050 0.010 42.130 0.560 ;
        RECT 42.970 0.010 43.050 0.560 ;
        RECT 43.890 0.010 43.970 0.560 ;
        RECT 44.810 0.010 44.890 0.560 ;
        RECT 45.730 0.010 45.810 0.560 ;
        RECT 46.650 0.010 46.730 0.560 ;
        RECT 47.570 0.010 47.650 0.560 ;
        RECT 48.490 0.010 48.570 0.560 ;
        RECT 49.410 0.010 49.490 0.560 ;
        RECT 50.330 0.010 50.410 0.560 ;
        RECT 51.250 0.010 51.330 0.560 ;
        RECT 52.170 0.010 52.250 0.560 ;
        RECT 53.090 0.010 53.170 0.560 ;
        RECT 54.010 0.010 54.090 0.560 ;
        RECT 54.930 0.010 55.010 0.560 ;
        RECT 55.850 0.010 55.930 0.560 ;
        RECT 56.770 0.010 56.850 0.560 ;
        RECT 57.690 0.010 57.770 0.560 ;
        RECT 58.610 0.010 58.690 0.560 ;
        RECT 59.530 0.010 59.610 0.560 ;
        RECT 60.450 0.010 60.530 0.560 ;
        RECT 61.370 0.010 61.450 0.560 ;
        RECT 62.290 0.010 62.370 0.560 ;
        RECT 63.210 0.010 63.290 0.560 ;
        RECT 64.130 0.010 64.210 0.560 ;
        RECT 65.050 0.010 65.130 0.560 ;
        RECT 65.970 0.010 66.050 0.560 ;
        RECT 66.890 0.010 66.970 0.560 ;
        RECT 67.810 0.010 67.890 0.560 ;
        RECT 68.730 0.010 68.810 0.560 ;
        RECT 69.650 0.010 69.730 0.560 ;
        RECT 70.570 0.010 70.650 0.560 ;
        RECT 71.490 0.010 71.570 0.560 ;
        RECT 72.410 0.010 72.490 0.560 ;
        RECT 73.330 0.010 73.410 0.560 ;
        RECT 74.250 0.010 74.330 0.560 ;
        RECT 75.170 0.010 75.250 0.560 ;
        RECT 76.090 0.010 76.170 0.560 ;
        RECT 77.010 0.010 77.090 0.560 ;
        RECT 77.930 0.010 78.010 0.560 ;
        RECT 78.850 0.010 78.930 0.560 ;
        RECT 79.770 0.010 79.850 0.560 ;
        RECT 80.690 0.010 80.770 0.560 ;
        RECT 81.610 0.010 81.690 0.560 ;
        RECT 82.530 0.010 82.610 0.560 ;
        RECT 83.450 0.010 83.530 0.560 ;
        RECT 84.370 0.010 84.450 0.560 ;
        RECT 85.290 0.010 85.370 0.560 ;
        RECT 86.210 0.010 86.290 0.560 ;
        RECT 87.130 0.010 87.210 0.560 ;
        RECT 88.050 0.010 88.130 0.560 ;
        RECT 88.970 0.010 89.050 0.560 ;
        RECT 89.890 0.010 89.970 0.560 ;
        RECT 90.810 0.010 90.890 0.560 ;
        RECT 91.730 0.010 91.810 0.560 ;
        RECT 92.650 0.010 92.730 0.560 ;
        RECT 93.570 0.010 93.650 0.560 ;
        RECT 94.490 0.010 94.570 0.560 ;
        RECT 95.410 0.010 95.490 0.560 ;
        RECT 96.330 0.010 96.410 0.560 ;
        RECT 97.250 0.010 97.330 0.560 ;
        RECT 98.170 0.010 98.250 0.560 ;
        RECT 99.090 0.010 267.530 0.560 ;
        RECT 268.370 0.010 268.450 0.560 ;
        RECT 269.290 0.010 269.370 0.560 ;
        RECT 270.210 0.010 270.290 0.560 ;
        RECT 271.130 0.010 271.210 0.560 ;
        RECT 272.050 0.010 272.130 0.560 ;
        RECT 272.970 0.010 273.050 0.560 ;
        RECT 273.890 0.010 273.970 0.560 ;
        RECT 274.810 0.010 274.890 0.560 ;
        RECT 275.730 0.010 275.810 0.560 ;
        RECT 276.650 0.010 276.730 0.560 ;
        RECT 277.570 0.010 277.650 0.560 ;
        RECT 278.490 0.010 278.570 0.560 ;
        RECT 279.410 0.010 279.490 0.560 ;
        RECT 280.330 0.010 280.410 0.560 ;
        RECT 281.250 0.010 281.330 0.560 ;
        RECT 282.170 0.010 282.250 0.560 ;
        RECT 283.090 0.010 283.170 0.560 ;
        RECT 284.010 0.010 284.090 0.560 ;
        RECT 284.930 0.010 285.010 0.560 ;
        RECT 285.850 0.010 285.930 0.560 ;
        RECT 286.770 0.010 286.850 0.560 ;
        RECT 287.690 0.010 287.770 0.560 ;
        RECT 288.610 0.010 288.690 0.560 ;
        RECT 289.530 0.010 289.610 0.560 ;
        RECT 290.450 0.010 290.530 0.560 ;
        RECT 291.370 0.010 291.450 0.560 ;
        RECT 292.290 0.010 292.370 0.560 ;
        RECT 293.210 0.010 293.290 0.560 ;
        RECT 294.130 0.010 294.210 0.560 ;
        RECT 295.050 0.010 295.130 0.560 ;
        RECT 295.970 0.010 296.050 0.560 ;
        RECT 296.890 0.010 296.970 0.560 ;
        RECT 297.810 0.010 297.890 0.560 ;
        RECT 298.730 0.010 298.810 0.560 ;
        RECT 299.650 0.010 299.730 0.560 ;
        RECT 300.570 0.010 300.650 0.560 ;
        RECT 301.490 0.010 301.570 0.560 ;
        RECT 302.410 0.010 302.490 0.560 ;
        RECT 303.330 0.010 303.410 0.560 ;
        RECT 304.250 0.010 304.330 0.560 ;
        RECT 305.170 0.010 305.250 0.560 ;
        RECT 306.090 0.010 306.170 0.560 ;
        RECT 307.010 0.010 307.090 0.560 ;
        RECT 307.930 0.010 308.010 0.560 ;
        RECT 308.850 0.010 308.930 0.560 ;
        RECT 309.770 0.010 309.850 0.560 ;
        RECT 310.690 0.010 310.770 0.560 ;
        RECT 311.610 0.010 311.690 0.560 ;
        RECT 312.530 0.010 312.610 0.560 ;
        RECT 313.450 0.010 313.530 0.560 ;
        RECT 314.370 0.010 314.450 0.560 ;
        RECT 315.290 0.010 315.370 0.560 ;
        RECT 316.210 0.010 316.290 0.560 ;
        RECT 317.130 0.010 317.210 0.560 ;
        RECT 318.050 0.010 318.130 0.560 ;
        RECT 318.970 0.010 319.050 0.560 ;
        RECT 319.890 0.010 362.390 0.560 ;
      LAYER met3 ;
        RECT 0.600 358.720 367.665 367.365 ;
        RECT 0.600 247.200 367.265 358.720 ;
        RECT 1.000 241.720 367.265 247.200 ;
        RECT 0.600 233.600 367.265 241.720 ;
        RECT 1.000 232.200 367.265 233.600 ;
        RECT 0.600 226.800 367.265 232.200 ;
        RECT 1.000 225.400 367.265 226.800 ;
        RECT 0.600 224.080 367.265 225.400 ;
        RECT 1.000 221.320 367.265 224.080 ;
        RECT 0.600 217.280 367.265 221.320 ;
        RECT 1.000 214.520 367.265 217.280 ;
        RECT 0.600 207.760 367.265 214.520 ;
        RECT 1.000 205.000 367.265 207.760 ;
        RECT 0.600 203.680 367.265 205.000 ;
        RECT 1.000 202.280 367.265 203.680 ;
        RECT 0.600 200.960 367.265 202.280 ;
        RECT 1.000 199.560 367.265 200.960 ;
        RECT 0.600 195.520 367.265 199.560 ;
        RECT 1.000 194.120 367.265 195.520 ;
        RECT 0.600 191.440 367.265 194.120 ;
        RECT 1.000 190.040 367.265 191.440 ;
        RECT 0.600 1.535 367.265 190.040 ;
      LAYER met4 ;
        RECT 222.935 3.575 309.745 359.545 ;
  END
END io_pad_ctrl
END LIBRARY

